VERSION 5.7 ;
  NOWIREEXTENSIONATPIN ON ;
  DIVIDERCHAR "/" ;
  BUSBITCHARS "[]" ;
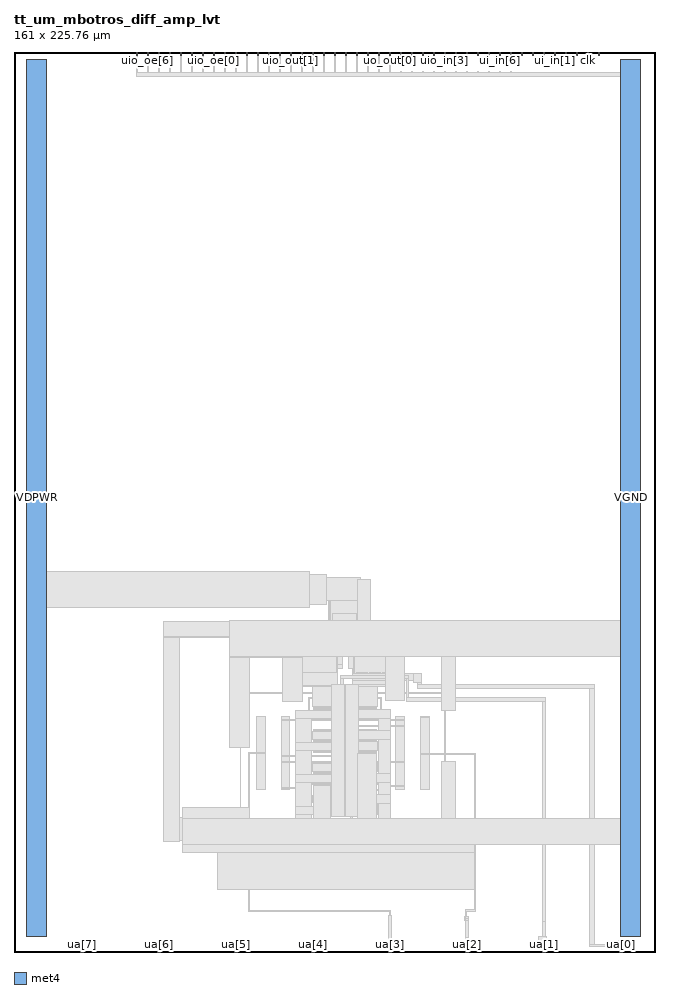
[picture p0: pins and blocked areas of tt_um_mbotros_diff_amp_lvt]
MACRO tt_um_mbotros_diff_amp_lvt
  CLASS BLOCK ;
  FOREIGN tt_um_mbotros_diff_amp_lvt ;
  ORIGIN 0.000 0.000 ;
  SIZE 161.000 BY 225.760 ;
  PIN clk
    DIRECTION INPUT ;
    USE SIGNAL ;
    PORT
      LAYER met4 ;
        RECT 143.830 224.760 144.130 225.760 ;
    END
  END clk
  PIN ena
    DIRECTION INPUT ;
    USE SIGNAL ;
    PORT
      LAYER met4 ;
        RECT 146.590 224.760 146.890 225.760 ;
    END
  END ena
  PIN rst_n
    DIRECTION INPUT ;
    USE SIGNAL ;
    PORT
      LAYER met4 ;
        RECT 141.070 224.760 141.370 225.760 ;
    END
  END rst_n
  PIN ua[0]
    DIRECTION INOUT ;
    USE SIGNAL ;
    ANTENNADIFFAREA 45.399998 ;
    PORT
      LAYER met4 ;
        RECT 151.810 0.000 152.710 1.000 ;
    END
  END ua[0]
  PIN ua[1]
    DIRECTION INOUT ;
    USE SIGNAL ;
    ANTENNADIFFAREA 42.500000 ;
    PORT
      LAYER met4 ;
        RECT 132.490 0.000 133.390 1.000 ;
    END
  END ua[1]
  PIN ua[2]
    DIRECTION INOUT ;
    USE SIGNAL ;
    PORT
      LAYER met4 ;
        RECT 113.170 0.000 114.070 1.000 ;
    END
  END ua[2]
  PIN ua[3]
    DIRECTION INOUT ;
    USE SIGNAL ;
    PORT
      LAYER met4 ;
        RECT 93.850 0.000 94.750 1.000 ;
    END
  END ua[3]
  PIN ua[4]
    DIRECTION INOUT ;
    USE SIGNAL ;
    PORT
      LAYER met4 ;
        RECT 74.530 0.000 75.430 1.000 ;
    END
  END ua[4]
  PIN ua[5]
    DIRECTION INOUT ;
    USE SIGNAL ;
    PORT
      LAYER met4 ;
        RECT 55.210 0.000 56.110 1.000 ;
    END
  END ua[5]
  PIN ua[6]
    DIRECTION INOUT ;
    USE SIGNAL ;
    PORT
      LAYER met4 ;
        RECT 35.890 0.000 36.790 1.000 ;
    END
  END ua[6]
  PIN ua[7]
    DIRECTION INOUT ;
    USE SIGNAL ;
    PORT
      LAYER met4 ;
        RECT 16.570 0.000 17.470 1.000 ;
    END
  END ua[7]
  PIN ui_in[0]
    DIRECTION INPUT ;
    USE SIGNAL ;
    PORT
      LAYER met4 ;
        RECT 138.310 224.760 138.610 225.760 ;
    END
  END ui_in[0]
  PIN ui_in[1]
    DIRECTION INPUT ;
    USE SIGNAL ;
    PORT
      LAYER met4 ;
        RECT 135.550 224.760 135.850 225.760 ;
    END
  END ui_in[1]
  PIN ui_in[2]
    DIRECTION INPUT ;
    USE SIGNAL ;
    PORT
      LAYER met4 ;
        RECT 132.790 224.760 133.090 225.760 ;
    END
  END ui_in[2]
  PIN ui_in[3]
    DIRECTION INPUT ;
    USE SIGNAL ;
    PORT
      LAYER met4 ;
        RECT 130.030 224.760 130.330 225.760 ;
    END
  END ui_in[3]
  PIN ui_in[4]
    DIRECTION INPUT ;
    USE SIGNAL ;
    PORT
      LAYER met4 ;
        RECT 127.270 224.760 127.570 225.760 ;
    END
  END ui_in[4]
  PIN ui_in[5]
    DIRECTION INPUT ;
    USE SIGNAL ;
    PORT
      LAYER met4 ;
        RECT 124.510 224.760 124.810 225.760 ;
    END
  END ui_in[5]
  PIN ui_in[6]
    DIRECTION INPUT ;
    USE SIGNAL ;
    PORT
      LAYER met4 ;
        RECT 121.750 224.760 122.050 225.760 ;
    END
  END ui_in[6]
  PIN ui_in[7]
    DIRECTION INPUT ;
    USE SIGNAL ;
    PORT
      LAYER met4 ;
        RECT 118.990 224.760 119.290 225.760 ;
    END
  END ui_in[7]
  PIN uio_in[0]
    DIRECTION INPUT ;
    USE SIGNAL ;
    PORT
      LAYER met4 ;
        RECT 116.230 224.760 116.530 225.760 ;
    END
  END uio_in[0]
  PIN uio_in[1]
    DIRECTION INPUT ;
    USE SIGNAL ;
    PORT
      LAYER met4 ;
        RECT 113.470 224.760 113.770 225.760 ;
    END
  END uio_in[1]
  PIN uio_in[2]
    DIRECTION INPUT ;
    USE SIGNAL ;
    PORT
      LAYER met4 ;
        RECT 110.710 224.760 111.010 225.760 ;
    END
  END uio_in[2]
  PIN uio_in[3]
    DIRECTION INPUT ;
    USE SIGNAL ;
    PORT
      LAYER met4 ;
        RECT 107.950 224.760 108.250 225.760 ;
    END
  END uio_in[3]
  PIN uio_in[4]
    DIRECTION INPUT ;
    USE SIGNAL ;
    PORT
      LAYER met4 ;
        RECT 105.190 224.760 105.490 225.760 ;
    END
  END uio_in[4]
  PIN uio_in[5]
    DIRECTION INPUT ;
    USE SIGNAL ;
    PORT
      LAYER met4 ;
        RECT 102.430 224.760 102.730 225.760 ;
    END
  END uio_in[5]
  PIN uio_in[6]
    DIRECTION INPUT ;
    USE SIGNAL ;
    PORT
      LAYER met4 ;
        RECT 99.670 224.760 99.970 225.760 ;
    END
  END uio_in[6]
  PIN uio_in[7]
    DIRECTION INPUT ;
    USE SIGNAL ;
    PORT
      LAYER met4 ;
        RECT 96.910 224.760 97.210 225.760 ;
    END
  END uio_in[7]
  PIN uio_oe[0]
    DIRECTION OUTPUT ;
    USE SIGNAL ;
    ANTENNADIFFAREA 129.679398 ;
    PORT
      LAYER met4 ;
        RECT 49.990 224.760 50.290 225.760 ;
    END
  END uio_oe[0]
  PIN uio_oe[1]
    DIRECTION OUTPUT ;
    USE SIGNAL ;
    ANTENNADIFFAREA 129.679398 ;
    PORT
      LAYER met4 ;
        RECT 47.230 224.760 47.530 225.760 ;
    END
  END uio_oe[1]
  PIN uio_oe[2]
    DIRECTION OUTPUT ;
    USE SIGNAL ;
    ANTENNADIFFAREA 129.679398 ;
    PORT
      LAYER met4 ;
        RECT 44.470 224.760 44.770 225.760 ;
    END
  END uio_oe[2]
  PIN uio_oe[3]
    DIRECTION OUTPUT ;
    USE SIGNAL ;
    ANTENNADIFFAREA 129.679398 ;
    PORT
      LAYER met4 ;
        RECT 41.710 224.760 42.010 225.760 ;
    END
  END uio_oe[3]
  PIN uio_oe[4]
    DIRECTION OUTPUT ;
    USE SIGNAL ;
    ANTENNADIFFAREA 129.679398 ;
    PORT
      LAYER met4 ;
        RECT 38.950 224.760 39.250 225.760 ;
    END
  END uio_oe[4]
  PIN uio_oe[5]
    DIRECTION OUTPUT ;
    USE SIGNAL ;
    ANTENNADIFFAREA 129.679398 ;
    PORT
      LAYER met4 ;
        RECT 36.190 224.760 36.490 225.760 ;
    END
  END uio_oe[5]
  PIN uio_oe[6]
    DIRECTION OUTPUT ;
    USE SIGNAL ;
    ANTENNADIFFAREA 129.679398 ;
    PORT
      LAYER met4 ;
        RECT 33.430 224.760 33.730 225.760 ;
    END
  END uio_oe[6]
  PIN uio_oe[7]
    DIRECTION OUTPUT ;
    USE SIGNAL ;
    ANTENNADIFFAREA 129.679398 ;
    PORT
      LAYER met4 ;
        RECT 30.670 224.760 30.970 225.760 ;
    END
  END uio_oe[7]
  PIN uio_out[0]
    DIRECTION OUTPUT ;
    USE SIGNAL ;
    ANTENNADIFFAREA 129.679398 ;
    PORT
      LAYER met4 ;
        RECT 72.070 224.760 72.370 225.760 ;
    END
  END uio_out[0]
  PIN uio_out[1]
    DIRECTION OUTPUT ;
    USE SIGNAL ;
    ANTENNADIFFAREA 129.679398 ;
    PORT
      LAYER met4 ;
        RECT 69.310 224.760 69.610 225.760 ;
    END
  END uio_out[1]
  PIN uio_out[2]
    DIRECTION OUTPUT ;
    USE SIGNAL ;
    ANTENNADIFFAREA 129.679398 ;
    PORT
      LAYER met4 ;
        RECT 66.550 224.760 66.850 225.760 ;
    END
  END uio_out[2]
  PIN uio_out[3]
    DIRECTION OUTPUT ;
    USE SIGNAL ;
    ANTENNADIFFAREA 129.679398 ;
    PORT
      LAYER met4 ;
        RECT 63.790 224.760 64.090 225.760 ;
    END
  END uio_out[3]
  PIN uio_out[4]
    DIRECTION OUTPUT ;
    USE SIGNAL ;
    ANTENNADIFFAREA 129.679398 ;
    PORT
      LAYER met4 ;
        RECT 61.030 224.760 61.330 225.760 ;
    END
  END uio_out[4]
  PIN uio_out[5]
    DIRECTION OUTPUT ;
    USE SIGNAL ;
    ANTENNADIFFAREA 129.679398 ;
    PORT
      LAYER met4 ;
        RECT 58.270 224.760 58.570 225.760 ;
    END
  END uio_out[5]
  PIN uio_out[6]
    DIRECTION OUTPUT ;
    USE SIGNAL ;
    ANTENNADIFFAREA 129.679398 ;
    PORT
      LAYER met4 ;
        RECT 55.510 224.760 55.810 225.760 ;
    END
  END uio_out[6]
  PIN uio_out[7]
    DIRECTION OUTPUT ;
    USE SIGNAL ;
    ANTENNADIFFAREA 129.679398 ;
    PORT
      LAYER met4 ;
        RECT 52.750 224.760 53.050 225.760 ;
    END
  END uio_out[7]
  PIN uo_out[0]
    DIRECTION OUTPUT ;
    USE SIGNAL ;
    ANTENNADIFFAREA 129.679398 ;
    PORT
      LAYER met4 ;
        RECT 94.150 224.760 94.450 225.760 ;
    END
  END uo_out[0]
  PIN uo_out[1]
    DIRECTION OUTPUT ;
    USE SIGNAL ;
    ANTENNADIFFAREA 129.679398 ;
    PORT
      LAYER met4 ;
        RECT 91.390 224.760 91.690 225.760 ;
    END
  END uo_out[1]
  PIN uo_out[2]
    DIRECTION OUTPUT ;
    USE SIGNAL ;
    ANTENNADIFFAREA 129.679398 ;
    PORT
      LAYER met4 ;
        RECT 88.630 224.760 88.930 225.760 ;
    END
  END uo_out[2]
  PIN uo_out[3]
    DIRECTION OUTPUT ;
    USE SIGNAL ;
    ANTENNADIFFAREA 129.679398 ;
    PORT
      LAYER met4 ;
        RECT 85.870 224.760 86.170 225.760 ;
    END
  END uo_out[3]
  PIN uo_out[4]
    DIRECTION OUTPUT ;
    USE SIGNAL ;
    ANTENNADIFFAREA 129.679398 ;
    PORT
      LAYER met4 ;
        RECT 83.110 224.760 83.410 225.760 ;
    END
  END uo_out[4]
  PIN uo_out[5]
    DIRECTION OUTPUT ;
    USE SIGNAL ;
    ANTENNADIFFAREA 129.679398 ;
    PORT
      LAYER met4 ;
        RECT 80.350 224.760 80.650 225.760 ;
    END
  END uo_out[5]
  PIN uo_out[6]
    DIRECTION OUTPUT ;
    USE SIGNAL ;
    ANTENNADIFFAREA 129.679398 ;
    PORT
      LAYER met4 ;
        RECT 77.590 224.760 77.890 225.760 ;
    END
  END uo_out[6]
  PIN uo_out[7]
    DIRECTION OUTPUT ;
    USE SIGNAL ;
    ANTENNADIFFAREA 129.679398 ;
    PORT
      LAYER met4 ;
        RECT 74.830 224.760 75.130 225.760 ;
    END
  END uo_out[7]
  PIN VGND
    DIRECTION INOUT ;
    USE GROUND ;
    PORT
      LAYER met4 ;
        RECT 152.250 3.900 157.250 223.900 ;
    END
  END VGND
  PIN VDPWR
    DIRECTION INOUT ;
    USE POWER ;
    PORT
      LAYER met4 ;
        RECT 3.100 3.900 8.100 223.900 ;
    END
  END VDPWR
  OBS
      LAYER pwell ;
        RECT 79.000 82.000 86.840 92.430 ;
        RECT 70.000 67.000 81.170 78.540 ;
        RECT 85.000 67.000 96.170 78.540 ;
        RECT 42.520 27.045 54.940 34.435 ;
      LAYER li1 ;
        RECT 79.180 92.080 86.660 92.250 ;
        RECT 79.180 83.180 79.350 92.080 ;
        RECT 86.490 91.940 86.660 92.080 ;
        RECT 79.830 89.440 82.680 91.600 ;
        RECT 83.160 89.440 86.010 91.600 ;
        RECT 86.490 90.940 87.920 91.940 ;
        RECT 77.860 82.350 79.350 83.180 ;
        RECT 79.830 82.830 82.680 84.990 ;
        RECT 83.160 82.830 86.010 84.990 ;
        RECT 86.490 83.200 86.660 90.940 ;
        RECT 86.490 82.350 87.980 83.200 ;
        RECT 77.860 82.200 87.980 82.350 ;
        RECT 77.860 82.180 86.660 82.200 ;
        RECT 69.060 78.360 70.260 78.430 ;
        RECT 95.900 78.360 97.180 78.630 ;
        RECT 69.060 78.190 80.990 78.360 ;
        RECT 69.060 77.560 70.350 78.190 ;
        RECT 70.180 68.400 70.350 77.560 ;
        RECT 70.830 75.550 73.680 77.710 ;
        RECT 74.160 75.550 77.010 77.710 ;
        RECT 77.490 75.550 80.340 77.710 ;
        RECT 80.820 72.240 80.990 78.190 ;
        RECT 85.180 78.190 97.180 78.360 ;
        RECT 85.180 72.260 85.350 78.190 ;
        RECT 85.830 75.550 88.680 77.710 ;
        RECT 89.160 75.550 92.010 77.710 ;
        RECT 92.490 75.550 95.340 77.710 ;
        RECT 95.820 77.690 97.180 78.190 ;
        RECT 80.820 71.370 82.150 72.240 ;
        RECT 69.000 67.350 70.350 68.400 ;
        RECT 70.830 67.830 73.680 69.990 ;
        RECT 74.160 67.830 77.010 69.990 ;
        RECT 77.490 67.830 80.340 69.990 ;
        RECT 80.820 67.350 80.990 71.370 ;
        RECT 84.140 71.340 85.350 72.260 ;
        RECT 69.000 67.190 80.990 67.350 ;
        RECT 70.180 67.180 80.990 67.190 ;
        RECT 85.180 67.350 85.350 71.340 ;
        RECT 85.830 67.830 88.680 69.990 ;
        RECT 89.160 67.830 92.010 69.990 ;
        RECT 92.490 67.830 95.340 69.990 ;
        RECT 95.820 67.680 95.990 77.690 ;
        RECT 95.820 67.350 97.260 67.680 ;
        RECT 85.180 67.180 97.260 67.350 ;
        RECT 95.900 66.680 97.260 67.180 ;
        RECT 56.735 64.855 108.185 65.025 ;
        RECT 56.735 64.800 56.905 64.855 ;
        RECT 55.550 63.590 56.905 64.800 ;
        RECT 70.160 63.740 71.460 64.855 ;
        RECT 75.145 63.630 80.905 63.800 ;
        RECT 85.145 63.630 90.905 63.800 ;
        RECT 93.890 63.760 95.190 64.855 ;
        RECT 56.735 53.580 56.905 63.590 ;
        RECT 55.570 52.370 56.905 53.580 ;
        RECT 60.830 53.250 62.990 58.980 ;
        RECT 66.990 53.250 69.150 58.980 ;
        RECT 75.060 58.420 75.230 63.460 ;
        RECT 75.540 58.420 75.710 63.460 ;
        RECT 76.020 58.420 76.190 63.460 ;
        RECT 76.500 58.420 76.670 63.460 ;
        RECT 76.980 58.420 77.150 63.460 ;
        RECT 77.460 58.420 77.630 63.460 ;
        RECT 77.940 58.420 78.110 63.460 ;
        RECT 78.420 58.420 78.590 63.460 ;
        RECT 78.900 58.420 79.070 63.460 ;
        RECT 79.380 58.420 79.550 63.460 ;
        RECT 79.860 58.420 80.030 63.460 ;
        RECT 80.340 58.420 80.510 63.460 ;
        RECT 80.820 58.420 80.990 63.460 ;
        RECT 85.060 58.420 85.230 63.460 ;
        RECT 85.540 58.420 85.710 63.460 ;
        RECT 86.020 58.420 86.190 63.460 ;
        RECT 86.500 58.420 86.670 63.460 ;
        RECT 86.980 58.420 87.150 63.460 ;
        RECT 87.460 58.420 87.630 63.460 ;
        RECT 87.940 58.420 88.110 63.460 ;
        RECT 88.420 58.420 88.590 63.460 ;
        RECT 88.900 58.420 89.070 63.460 ;
        RECT 89.380 58.420 89.550 63.460 ;
        RECT 89.860 58.420 90.030 63.460 ;
        RECT 90.340 58.420 90.510 63.460 ;
        RECT 90.820 58.420 90.990 63.460 ;
        RECT 108.015 62.690 108.185 64.855 ;
        RECT 108.015 61.480 109.390 62.690 ;
        RECT 75.145 58.080 80.905 58.250 ;
        RECT 85.145 58.080 90.905 58.250 ;
        RECT 75.145 55.630 80.905 55.800 ;
        RECT 85.145 55.630 90.905 55.800 ;
        RECT 42.700 34.255 43.670 35.340 ;
        RECT 56.735 34.740 56.905 52.370 ;
        RECT 60.830 47.040 62.990 52.770 ;
        RECT 66.990 47.040 69.150 52.770 ;
        RECT 75.060 50.420 75.230 55.460 ;
        RECT 75.540 50.420 75.710 55.460 ;
        RECT 76.020 50.420 76.190 55.460 ;
        RECT 76.500 50.420 76.670 55.460 ;
        RECT 76.980 50.420 77.150 55.460 ;
        RECT 77.460 50.420 77.630 55.460 ;
        RECT 77.940 50.420 78.110 55.460 ;
        RECT 78.420 50.420 78.590 55.460 ;
        RECT 78.900 50.420 79.070 55.460 ;
        RECT 79.380 50.420 79.550 55.460 ;
        RECT 79.860 50.420 80.030 55.460 ;
        RECT 80.340 50.420 80.510 55.460 ;
        RECT 80.820 50.420 80.990 55.460 ;
        RECT 85.060 50.420 85.230 55.460 ;
        RECT 85.540 50.420 85.710 55.460 ;
        RECT 86.020 50.420 86.190 55.460 ;
        RECT 86.500 50.420 86.670 55.460 ;
        RECT 86.980 50.420 87.150 55.460 ;
        RECT 87.460 50.420 87.630 55.460 ;
        RECT 87.940 50.420 88.110 55.460 ;
        RECT 88.420 50.420 88.590 55.460 ;
        RECT 88.900 50.420 89.070 55.460 ;
        RECT 89.380 50.420 89.550 55.460 ;
        RECT 89.860 50.420 90.030 55.460 ;
        RECT 90.340 50.420 90.510 55.460 ;
        RECT 90.820 50.420 90.990 55.460 ;
        RECT 95.830 53.250 97.990 58.980 ;
        RECT 101.990 53.250 104.150 58.980 ;
        RECT 75.145 50.080 80.905 50.250 ;
        RECT 85.145 50.080 90.905 50.250 ;
        RECT 87.850 48.540 89.210 49.410 ;
        RECT 75.145 47.630 80.905 47.800 ;
        RECT 85.145 47.630 90.905 47.800 ;
        RECT 60.830 40.830 62.990 46.560 ;
        RECT 66.990 40.830 69.150 46.560 ;
        RECT 75.060 42.420 75.230 47.460 ;
        RECT 75.540 42.420 75.710 47.460 ;
        RECT 76.020 42.420 76.190 47.460 ;
        RECT 76.500 42.420 76.670 47.460 ;
        RECT 76.980 42.420 77.150 47.460 ;
        RECT 77.460 42.420 77.630 47.460 ;
        RECT 77.940 42.420 78.110 47.460 ;
        RECT 78.420 42.420 78.590 47.460 ;
        RECT 78.900 42.420 79.070 47.460 ;
        RECT 79.380 42.420 79.550 47.460 ;
        RECT 79.860 42.420 80.030 47.460 ;
        RECT 80.340 42.420 80.510 47.460 ;
        RECT 80.820 42.420 80.990 47.460 ;
        RECT 85.060 42.420 85.230 47.460 ;
        RECT 85.540 42.420 85.710 47.460 ;
        RECT 86.020 42.420 86.190 47.460 ;
        RECT 86.500 42.420 86.670 47.460 ;
        RECT 86.980 42.420 87.150 47.460 ;
        RECT 87.460 42.420 87.630 47.460 ;
        RECT 87.940 42.420 88.110 47.460 ;
        RECT 88.420 42.420 88.590 47.460 ;
        RECT 88.900 42.420 89.070 47.460 ;
        RECT 89.380 42.420 89.550 47.460 ;
        RECT 89.860 42.420 90.030 47.460 ;
        RECT 90.340 42.420 90.510 47.460 ;
        RECT 90.820 42.420 90.990 47.460 ;
        RECT 95.830 47.040 97.990 52.770 ;
        RECT 101.990 47.040 104.150 52.770 ;
        RECT 108.015 47.280 108.185 61.480 ;
        RECT 75.145 42.080 80.905 42.250 ;
        RECT 85.145 42.080 90.905 42.250 ;
        RECT 76.870 40.470 78.230 41.340 ;
        RECT 95.830 40.830 97.990 46.560 ;
        RECT 101.990 40.830 104.150 46.560 ;
        RECT 108.015 46.070 109.420 47.280 ;
        RECT 75.145 39.630 80.905 39.800 ;
        RECT 85.145 39.630 90.905 39.800 ;
        RECT 54.610 34.255 56.905 34.740 ;
        RECT 75.060 34.420 75.230 39.460 ;
        RECT 75.540 34.420 75.710 39.460 ;
        RECT 76.020 34.420 76.190 39.460 ;
        RECT 76.500 34.420 76.670 39.460 ;
        RECT 76.980 34.420 77.150 39.460 ;
        RECT 77.460 34.420 77.630 39.460 ;
        RECT 77.940 34.420 78.110 39.460 ;
        RECT 78.420 34.420 78.590 39.460 ;
        RECT 78.900 34.420 79.070 39.460 ;
        RECT 79.380 34.420 79.550 39.460 ;
        RECT 79.860 34.420 80.030 39.460 ;
        RECT 80.340 34.420 80.510 39.460 ;
        RECT 80.820 34.420 80.990 39.460 ;
        RECT 85.060 34.420 85.230 39.460 ;
        RECT 85.540 34.420 85.710 39.460 ;
        RECT 86.020 34.420 86.190 39.460 ;
        RECT 86.500 34.420 86.670 39.460 ;
        RECT 86.980 34.420 87.150 39.460 ;
        RECT 87.460 34.420 87.630 39.460 ;
        RECT 87.940 34.420 88.110 39.460 ;
        RECT 88.420 34.420 88.590 39.460 ;
        RECT 88.900 34.420 89.070 39.460 ;
        RECT 89.380 34.420 89.550 39.460 ;
        RECT 89.860 34.420 90.030 39.460 ;
        RECT 90.340 34.420 90.510 39.460 ;
        RECT 90.820 34.420 90.990 39.460 ;
        RECT 42.700 34.085 56.905 34.255 ;
        RECT 42.700 27.395 42.870 34.085 ;
        RECT 54.590 33.830 56.905 34.085 ;
        RECT 75.145 34.080 80.905 34.250 ;
        RECT 85.145 34.080 90.905 34.250 ;
        RECT 43.350 27.875 45.510 33.605 ;
        RECT 51.950 27.875 54.110 33.605 ;
        RECT 54.590 27.395 54.760 33.830 ;
        RECT 56.735 31.160 56.905 33.830 ;
        RECT 108.015 33.440 108.185 46.070 ;
        RECT 108.015 32.230 109.400 33.440 ;
        RECT 56.735 30.095 58.050 31.160 ;
        RECT 108.015 30.095 108.185 32.230 ;
        RECT 56.735 29.925 108.185 30.095 ;
        RECT 42.700 27.225 54.760 27.395 ;
        RECT 42.700 26.110 43.670 27.225 ;
        RECT 56.220 26.385 57.390 27.540 ;
        RECT 114.130 26.385 115.250 27.040 ;
        RECT 51.085 26.215 115.250 26.385 ;
        RECT 51.085 17.515 51.255 26.215 ;
        RECT 52.080 20.145 52.250 25.675 ;
        RECT 52.420 25.590 57.460 25.760 ;
        RECT 52.420 24.800 57.460 24.970 ;
        RECT 52.420 24.010 57.460 24.180 ;
        RECT 52.420 23.220 57.460 23.390 ;
        RECT 52.420 22.430 57.460 22.600 ;
        RECT 52.420 21.640 57.460 21.810 ;
        RECT 52.420 20.850 57.460 21.020 ;
        RECT 52.420 20.060 57.460 20.230 ;
        RECT 57.630 20.145 57.800 25.675 ;
        RECT 60.080 20.145 60.250 25.675 ;
        RECT 60.420 25.590 65.460 25.760 ;
        RECT 60.420 24.800 65.460 24.970 ;
        RECT 60.420 24.010 65.460 24.180 ;
        RECT 60.420 23.220 65.460 23.390 ;
        RECT 60.420 22.430 65.460 22.600 ;
        RECT 60.420 21.640 65.460 21.810 ;
        RECT 60.420 20.850 65.460 21.020 ;
        RECT 60.420 20.060 65.460 20.230 ;
        RECT 65.630 20.145 65.800 25.675 ;
        RECT 68.080 20.145 68.250 25.675 ;
        RECT 68.420 25.590 73.460 25.760 ;
        RECT 68.420 24.800 73.460 24.970 ;
        RECT 68.420 24.010 73.460 24.180 ;
        RECT 68.420 23.220 73.460 23.390 ;
        RECT 68.420 22.430 73.460 22.600 ;
        RECT 68.420 21.640 73.460 21.810 ;
        RECT 68.420 20.850 73.460 21.020 ;
        RECT 68.420 20.060 73.460 20.230 ;
        RECT 73.630 20.145 73.800 25.675 ;
        RECT 76.080 20.145 76.250 25.675 ;
        RECT 76.420 25.590 81.460 25.760 ;
        RECT 76.420 24.800 81.460 24.970 ;
        RECT 76.420 24.010 81.460 24.180 ;
        RECT 76.420 23.220 81.460 23.390 ;
        RECT 76.420 22.430 81.460 22.600 ;
        RECT 76.420 21.640 81.460 21.810 ;
        RECT 76.420 20.850 81.460 21.020 ;
        RECT 76.420 20.060 81.460 20.230 ;
        RECT 81.630 20.145 81.800 25.675 ;
        RECT 82.340 25.040 83.510 26.215 ;
        RECT 84.080 20.145 84.250 25.675 ;
        RECT 84.420 25.590 89.460 25.760 ;
        RECT 84.420 24.800 89.460 24.970 ;
        RECT 84.420 24.010 89.460 24.180 ;
        RECT 84.420 23.220 89.460 23.390 ;
        RECT 84.420 22.430 89.460 22.600 ;
        RECT 84.420 21.640 89.460 21.810 ;
        RECT 84.420 20.850 89.460 21.020 ;
        RECT 84.420 20.060 89.460 20.230 ;
        RECT 89.630 20.145 89.800 25.675 ;
        RECT 92.080 20.145 92.250 25.675 ;
        RECT 92.420 25.590 97.460 25.760 ;
        RECT 92.420 24.800 97.460 24.970 ;
        RECT 92.420 24.010 97.460 24.180 ;
        RECT 92.420 23.220 97.460 23.390 ;
        RECT 92.420 22.430 97.460 22.600 ;
        RECT 92.420 21.640 97.460 21.810 ;
        RECT 92.420 20.850 97.460 21.020 ;
        RECT 92.420 20.060 97.460 20.230 ;
        RECT 97.630 20.145 97.800 25.675 ;
        RECT 100.080 20.145 100.250 25.675 ;
        RECT 100.420 25.590 105.460 25.760 ;
        RECT 100.420 24.800 105.460 24.970 ;
        RECT 100.420 24.010 105.460 24.180 ;
        RECT 100.420 23.220 105.460 23.390 ;
        RECT 100.420 22.430 105.460 22.600 ;
        RECT 100.420 21.640 105.460 21.810 ;
        RECT 100.420 20.850 105.460 21.020 ;
        RECT 100.420 20.060 105.460 20.230 ;
        RECT 105.630 20.145 105.800 25.675 ;
        RECT 108.080 20.145 108.250 25.675 ;
        RECT 108.420 25.590 113.460 25.760 ;
        RECT 108.420 24.800 113.460 24.970 ;
        RECT 108.420 24.010 113.460 24.180 ;
        RECT 108.420 23.220 113.460 23.390 ;
        RECT 108.420 22.430 113.460 22.600 ;
        RECT 108.420 21.640 113.460 21.810 ;
        RECT 108.420 20.850 113.460 21.020 ;
        RECT 108.420 20.060 113.460 20.230 ;
        RECT 113.630 20.145 113.800 25.675 ;
        RECT 114.130 25.520 115.250 26.215 ;
        RECT 114.315 17.520 114.485 25.520 ;
        RECT 113.010 17.515 114.485 17.520 ;
        RECT 51.085 17.345 114.485 17.515 ;
        RECT 51.390 16.200 52.730 17.345 ;
        RECT 63.550 16.180 64.800 17.345 ;
        RECT 78.870 16.220 80.100 17.345 ;
        RECT 97.130 16.290 98.460 17.345 ;
        RECT 113.010 16.380 114.340 17.345 ;
      LAYER met1 ;
        RECT 86.560 91.930 87.920 91.940 ;
        RECT 79.850 89.495 82.660 91.540 ;
        RECT 83.180 89.495 85.990 91.540 ;
        RECT 86.560 90.940 88.330 91.930 ;
        RECT 87.240 90.930 88.330 90.940 ;
        RECT 77.860 82.180 79.220 83.180 ;
        RECT 79.850 82.890 82.660 84.935 ;
        RECT 83.180 82.890 85.990 84.935 ;
        RECT 86.620 82.200 87.980 83.200 ;
        RECT 96.200 78.630 97.130 78.640 ;
        RECT 69.060 77.560 70.260 78.430 ;
        RECT 95.900 77.690 97.180 78.630 ;
        RECT 96.200 77.660 97.130 77.690 ;
        RECT 70.850 75.605 73.660 77.650 ;
        RECT 74.180 75.605 76.990 77.650 ;
        RECT 77.510 75.605 80.320 77.650 ;
        RECT 85.850 75.605 88.660 77.650 ;
        RECT 89.180 75.605 91.990 77.650 ;
        RECT 92.510 75.605 95.320 77.650 ;
        RECT 80.950 71.370 82.150 72.240 ;
        RECT 84.140 71.340 85.230 72.260 ;
        RECT 69.000 67.190 70.300 68.400 ;
        RECT 70.850 67.890 73.660 69.935 ;
        RECT 74.180 67.890 76.990 69.935 ;
        RECT 77.510 67.890 80.320 69.935 ;
        RECT 85.850 67.890 88.660 69.935 ;
        RECT 89.180 67.890 91.990 69.935 ;
        RECT 92.510 67.890 95.320 69.935 ;
        RECT 96.310 67.680 97.240 67.760 ;
        RECT 95.900 66.680 97.260 67.680 ;
        RECT 55.550 63.590 56.850 64.800 ;
        RECT 70.160 63.740 71.460 64.950 ;
        RECT 73.915 63.580 80.915 63.880 ;
        RECT 85.150 63.800 92.150 63.880 ;
        RECT 85.145 63.630 92.150 63.800 ;
        RECT 93.890 63.760 95.190 64.970 ;
        RECT 85.150 63.580 92.150 63.630 ;
        RECT 55.570 52.370 56.870 53.580 ;
        RECT 60.890 53.270 62.935 58.960 ;
        RECT 66.980 58.300 69.160 58.990 ;
        RECT 73.915 58.300 74.215 63.580 ;
        RECT 75.030 63.135 75.260 63.440 ;
        RECT 74.950 62.875 75.310 63.135 ;
        RECT 75.030 62.560 75.260 62.875 ;
        RECT 74.950 62.300 75.310 62.560 ;
        RECT 75.030 61.950 75.260 62.300 ;
        RECT 74.950 61.690 75.310 61.950 ;
        RECT 75.030 58.440 75.260 61.690 ;
        RECT 75.510 60.435 75.740 63.440 ;
        RECT 75.990 63.130 76.220 63.440 ;
        RECT 75.925 62.870 76.285 63.130 ;
        RECT 75.990 62.565 76.220 62.870 ;
        RECT 75.925 62.305 76.285 62.565 ;
        RECT 75.990 61.955 76.220 62.305 ;
        RECT 75.925 61.695 76.285 61.955 ;
        RECT 75.445 60.175 75.805 60.435 ;
        RECT 75.510 59.720 75.740 60.175 ;
        RECT 75.445 59.460 75.805 59.720 ;
        RECT 75.510 59.040 75.740 59.460 ;
        RECT 75.445 58.780 75.805 59.040 ;
        RECT 75.510 58.440 75.740 58.780 ;
        RECT 75.990 58.440 76.220 61.695 ;
        RECT 76.470 60.435 76.700 63.440 ;
        RECT 76.950 63.130 77.180 63.440 ;
        RECT 76.885 62.870 77.245 63.130 ;
        RECT 76.950 62.565 77.180 62.870 ;
        RECT 76.885 62.305 77.245 62.565 ;
        RECT 76.950 61.955 77.180 62.305 ;
        RECT 76.885 61.695 77.245 61.955 ;
        RECT 76.405 60.175 76.765 60.435 ;
        RECT 76.470 59.720 76.700 60.175 ;
        RECT 76.405 59.460 76.765 59.720 ;
        RECT 76.470 59.040 76.700 59.460 ;
        RECT 76.405 58.780 76.765 59.040 ;
        RECT 76.470 58.440 76.700 58.780 ;
        RECT 76.950 58.440 77.180 61.695 ;
        RECT 77.430 60.435 77.660 63.440 ;
        RECT 77.910 63.130 78.140 63.440 ;
        RECT 77.845 62.870 78.205 63.130 ;
        RECT 77.910 62.565 78.140 62.870 ;
        RECT 77.845 62.305 78.205 62.565 ;
        RECT 77.910 61.955 78.140 62.305 ;
        RECT 77.845 61.695 78.205 61.955 ;
        RECT 77.365 60.175 77.725 60.435 ;
        RECT 77.430 59.720 77.660 60.175 ;
        RECT 77.365 59.460 77.725 59.720 ;
        RECT 77.430 59.040 77.660 59.460 ;
        RECT 77.365 58.780 77.725 59.040 ;
        RECT 77.430 58.440 77.660 58.780 ;
        RECT 77.910 58.440 78.140 61.695 ;
        RECT 78.390 60.435 78.620 63.440 ;
        RECT 78.870 63.130 79.100 63.440 ;
        RECT 78.805 62.870 79.165 63.130 ;
        RECT 78.870 62.565 79.100 62.870 ;
        RECT 78.805 62.305 79.165 62.565 ;
        RECT 78.870 61.955 79.100 62.305 ;
        RECT 78.805 61.695 79.165 61.955 ;
        RECT 78.325 60.175 78.685 60.435 ;
        RECT 78.390 59.720 78.620 60.175 ;
        RECT 78.325 59.460 78.685 59.720 ;
        RECT 78.390 59.040 78.620 59.460 ;
        RECT 78.325 58.780 78.685 59.040 ;
        RECT 78.390 58.440 78.620 58.780 ;
        RECT 78.870 58.440 79.100 61.695 ;
        RECT 79.350 60.435 79.580 63.440 ;
        RECT 79.830 63.130 80.060 63.440 ;
        RECT 79.765 62.870 80.125 63.130 ;
        RECT 79.830 62.565 80.060 62.870 ;
        RECT 79.770 62.305 80.130 62.565 ;
        RECT 79.830 61.955 80.060 62.305 ;
        RECT 79.765 61.695 80.125 61.955 ;
        RECT 79.285 60.175 79.645 60.435 ;
        RECT 79.350 59.720 79.580 60.175 ;
        RECT 79.285 59.460 79.645 59.720 ;
        RECT 79.350 59.040 79.580 59.460 ;
        RECT 79.285 58.780 79.645 59.040 ;
        RECT 79.350 58.440 79.580 58.780 ;
        RECT 79.830 58.440 80.060 61.695 ;
        RECT 80.310 60.435 80.540 63.440 ;
        RECT 80.790 63.130 81.020 63.440 ;
        RECT 85.030 63.135 85.260 63.440 ;
        RECT 80.725 62.870 81.085 63.130 ;
        RECT 84.950 62.875 85.310 63.135 ;
        RECT 80.790 62.565 81.020 62.870 ;
        RECT 80.725 62.305 81.085 62.565 ;
        RECT 85.030 62.560 85.260 62.875 ;
        RECT 80.790 61.955 81.020 62.305 ;
        RECT 84.950 62.300 85.310 62.560 ;
        RECT 80.720 61.695 81.080 61.955 ;
        RECT 85.030 61.950 85.260 62.300 ;
        RECT 80.250 60.175 80.610 60.435 ;
        RECT 80.310 59.720 80.540 60.175 ;
        RECT 80.245 59.460 80.605 59.720 ;
        RECT 80.310 59.040 80.540 59.460 ;
        RECT 80.250 58.780 80.610 59.040 ;
        RECT 80.310 58.440 80.540 58.780 ;
        RECT 80.790 58.440 81.020 61.695 ;
        RECT 84.950 61.690 85.310 61.950 ;
        RECT 85.030 58.440 85.260 61.690 ;
        RECT 85.510 60.435 85.740 63.440 ;
        RECT 85.990 63.130 86.220 63.440 ;
        RECT 85.925 62.870 86.285 63.130 ;
        RECT 85.990 62.565 86.220 62.870 ;
        RECT 85.925 62.305 86.285 62.565 ;
        RECT 85.990 61.955 86.220 62.305 ;
        RECT 85.925 61.695 86.285 61.955 ;
        RECT 85.445 60.175 85.805 60.435 ;
        RECT 85.510 59.720 85.740 60.175 ;
        RECT 85.445 59.460 85.805 59.720 ;
        RECT 85.510 59.040 85.740 59.460 ;
        RECT 85.445 58.780 85.805 59.040 ;
        RECT 85.510 58.440 85.740 58.780 ;
        RECT 85.990 58.440 86.220 61.695 ;
        RECT 86.470 60.435 86.700 63.440 ;
        RECT 86.950 63.130 87.180 63.440 ;
        RECT 86.885 62.870 87.245 63.130 ;
        RECT 86.950 62.565 87.180 62.870 ;
        RECT 86.885 62.305 87.245 62.565 ;
        RECT 86.950 61.955 87.180 62.305 ;
        RECT 86.885 61.695 87.245 61.955 ;
        RECT 86.405 60.175 86.765 60.435 ;
        RECT 86.470 59.720 86.700 60.175 ;
        RECT 86.405 59.460 86.765 59.720 ;
        RECT 86.470 59.040 86.700 59.460 ;
        RECT 86.405 58.780 86.765 59.040 ;
        RECT 86.470 58.440 86.700 58.780 ;
        RECT 86.950 58.440 87.180 61.695 ;
        RECT 87.430 60.435 87.660 63.440 ;
        RECT 87.910 63.130 88.140 63.440 ;
        RECT 87.845 62.870 88.205 63.130 ;
        RECT 87.910 62.565 88.140 62.870 ;
        RECT 87.845 62.305 88.205 62.565 ;
        RECT 87.910 61.955 88.140 62.305 ;
        RECT 87.845 61.695 88.205 61.955 ;
        RECT 87.365 60.175 87.725 60.435 ;
        RECT 87.430 59.720 87.660 60.175 ;
        RECT 87.365 59.460 87.725 59.720 ;
        RECT 87.430 59.040 87.660 59.460 ;
        RECT 87.365 58.780 87.725 59.040 ;
        RECT 87.430 58.440 87.660 58.780 ;
        RECT 87.910 58.440 88.140 61.695 ;
        RECT 88.390 60.435 88.620 63.440 ;
        RECT 88.870 63.130 89.100 63.440 ;
        RECT 88.805 62.870 89.165 63.130 ;
        RECT 88.870 62.565 89.100 62.870 ;
        RECT 88.805 62.305 89.165 62.565 ;
        RECT 88.870 61.955 89.100 62.305 ;
        RECT 88.805 61.695 89.165 61.955 ;
        RECT 88.325 60.175 88.685 60.435 ;
        RECT 88.390 59.720 88.620 60.175 ;
        RECT 88.325 59.460 88.685 59.720 ;
        RECT 88.390 59.040 88.620 59.460 ;
        RECT 88.325 58.780 88.685 59.040 ;
        RECT 88.390 58.440 88.620 58.780 ;
        RECT 88.870 58.440 89.100 61.695 ;
        RECT 89.350 60.435 89.580 63.440 ;
        RECT 89.830 63.130 90.060 63.440 ;
        RECT 89.765 62.870 90.125 63.130 ;
        RECT 89.830 62.565 90.060 62.870 ;
        RECT 89.770 62.305 90.130 62.565 ;
        RECT 89.830 61.955 90.060 62.305 ;
        RECT 89.765 61.695 90.125 61.955 ;
        RECT 89.285 60.175 89.645 60.435 ;
        RECT 89.350 59.720 89.580 60.175 ;
        RECT 89.285 59.460 89.645 59.720 ;
        RECT 89.350 59.040 89.580 59.460 ;
        RECT 89.285 58.780 89.645 59.040 ;
        RECT 89.350 58.440 89.580 58.780 ;
        RECT 89.830 58.440 90.060 61.695 ;
        RECT 90.310 60.435 90.540 63.440 ;
        RECT 90.790 63.130 91.020 63.440 ;
        RECT 90.725 62.870 91.085 63.130 ;
        RECT 90.790 62.565 91.020 62.870 ;
        RECT 90.725 62.305 91.085 62.565 ;
        RECT 90.790 61.955 91.020 62.305 ;
        RECT 90.720 61.695 91.080 61.955 ;
        RECT 90.250 60.175 90.610 60.435 ;
        RECT 90.310 59.720 90.540 60.175 ;
        RECT 90.245 59.460 90.605 59.720 ;
        RECT 90.310 59.040 90.540 59.460 ;
        RECT 90.250 58.780 90.610 59.040 ;
        RECT 90.310 58.440 90.540 58.780 ;
        RECT 90.790 58.440 91.020 61.695 ;
        RECT 91.850 58.300 92.150 63.580 ;
        RECT 108.090 61.480 109.390 62.690 ;
        RECT 95.820 58.300 97.980 58.990 ;
        RECT 66.980 58.000 80.915 58.300 ;
        RECT 85.100 58.000 97.980 58.300 ;
        RECT 60.890 47.060 62.935 52.750 ;
        RECT 66.980 49.300 69.160 58.000 ;
        RECT 95.820 56.875 97.980 58.000 ;
        RECT 81.230 56.575 97.980 56.875 ;
        RECT 81.230 55.880 81.530 56.575 ;
        RECT 75.145 55.580 81.530 55.880 ;
        RECT 75.030 55.135 75.260 55.440 ;
        RECT 74.950 54.875 75.310 55.135 ;
        RECT 75.030 54.560 75.260 54.875 ;
        RECT 74.950 54.300 75.310 54.560 ;
        RECT 75.030 53.950 75.260 54.300 ;
        RECT 74.950 53.690 75.310 53.950 ;
        RECT 75.030 50.440 75.260 53.690 ;
        RECT 75.510 52.435 75.740 55.440 ;
        RECT 75.990 55.130 76.220 55.440 ;
        RECT 75.925 54.870 76.285 55.130 ;
        RECT 75.990 54.565 76.220 54.870 ;
        RECT 75.925 54.305 76.285 54.565 ;
        RECT 75.990 53.955 76.220 54.305 ;
        RECT 75.925 53.695 76.285 53.955 ;
        RECT 75.445 52.175 75.805 52.435 ;
        RECT 75.510 51.720 75.740 52.175 ;
        RECT 75.445 51.460 75.805 51.720 ;
        RECT 75.510 51.040 75.740 51.460 ;
        RECT 75.445 50.780 75.805 51.040 ;
        RECT 75.510 50.440 75.740 50.780 ;
        RECT 75.990 50.440 76.220 53.695 ;
        RECT 76.470 52.435 76.700 55.440 ;
        RECT 76.950 55.130 77.180 55.440 ;
        RECT 76.885 54.870 77.245 55.130 ;
        RECT 76.950 54.565 77.180 54.870 ;
        RECT 76.885 54.305 77.245 54.565 ;
        RECT 76.950 53.955 77.180 54.305 ;
        RECT 76.885 53.695 77.245 53.955 ;
        RECT 76.405 52.175 76.765 52.435 ;
        RECT 76.470 51.720 76.700 52.175 ;
        RECT 76.405 51.460 76.765 51.720 ;
        RECT 76.470 51.040 76.700 51.460 ;
        RECT 76.405 50.780 76.765 51.040 ;
        RECT 76.470 50.440 76.700 50.780 ;
        RECT 76.950 50.440 77.180 53.695 ;
        RECT 77.430 52.435 77.660 55.440 ;
        RECT 77.910 55.130 78.140 55.440 ;
        RECT 77.845 54.870 78.205 55.130 ;
        RECT 77.910 54.565 78.140 54.870 ;
        RECT 77.845 54.305 78.205 54.565 ;
        RECT 77.910 53.955 78.140 54.305 ;
        RECT 77.845 53.695 78.205 53.955 ;
        RECT 77.365 52.175 77.725 52.435 ;
        RECT 77.430 51.720 77.660 52.175 ;
        RECT 77.365 51.460 77.725 51.720 ;
        RECT 77.430 51.040 77.660 51.460 ;
        RECT 77.365 50.780 77.725 51.040 ;
        RECT 77.430 50.440 77.660 50.780 ;
        RECT 77.910 50.440 78.140 53.695 ;
        RECT 78.390 52.435 78.620 55.440 ;
        RECT 78.870 55.130 79.100 55.440 ;
        RECT 78.805 54.870 79.165 55.130 ;
        RECT 78.870 54.565 79.100 54.870 ;
        RECT 78.805 54.305 79.165 54.565 ;
        RECT 78.870 53.955 79.100 54.305 ;
        RECT 78.805 53.695 79.165 53.955 ;
        RECT 78.325 52.175 78.685 52.435 ;
        RECT 78.390 51.720 78.620 52.175 ;
        RECT 78.325 51.460 78.685 51.720 ;
        RECT 78.390 51.040 78.620 51.460 ;
        RECT 78.325 50.780 78.685 51.040 ;
        RECT 78.390 50.440 78.620 50.780 ;
        RECT 78.870 50.440 79.100 53.695 ;
        RECT 79.350 52.435 79.580 55.440 ;
        RECT 79.830 55.130 80.060 55.440 ;
        RECT 79.765 54.870 80.125 55.130 ;
        RECT 79.830 54.565 80.060 54.870 ;
        RECT 79.770 54.305 80.130 54.565 ;
        RECT 79.830 53.955 80.060 54.305 ;
        RECT 79.765 53.695 80.125 53.955 ;
        RECT 79.285 52.175 79.645 52.435 ;
        RECT 79.350 51.720 79.580 52.175 ;
        RECT 79.285 51.460 79.645 51.720 ;
        RECT 79.350 51.040 79.580 51.460 ;
        RECT 79.285 50.780 79.645 51.040 ;
        RECT 79.350 50.440 79.580 50.780 ;
        RECT 79.830 50.440 80.060 53.695 ;
        RECT 80.310 52.435 80.540 55.440 ;
        RECT 80.790 55.130 81.020 55.440 ;
        RECT 80.725 54.870 81.085 55.130 ;
        RECT 80.790 54.565 81.020 54.870 ;
        RECT 80.725 54.305 81.085 54.565 ;
        RECT 80.790 53.955 81.020 54.305 ;
        RECT 80.720 53.695 81.080 53.955 ;
        RECT 80.250 52.175 80.610 52.435 ;
        RECT 80.310 51.720 80.540 52.175 ;
        RECT 80.245 51.460 80.605 51.720 ;
        RECT 80.310 51.040 80.540 51.460 ;
        RECT 80.250 50.780 80.610 51.040 ;
        RECT 80.310 50.440 80.540 50.780 ;
        RECT 80.790 50.440 81.020 53.695 ;
        RECT 81.230 50.300 81.530 55.580 ;
        RECT 75.150 50.250 81.530 50.300 ;
        RECT 75.145 50.080 81.530 50.250 ;
        RECT 75.150 50.000 81.530 50.080 ;
        RECT 84.505 55.580 90.910 55.880 ;
        RECT 84.505 50.300 84.805 55.580 ;
        RECT 85.030 55.135 85.260 55.440 ;
        RECT 84.950 54.875 85.310 55.135 ;
        RECT 85.030 54.560 85.260 54.875 ;
        RECT 84.950 54.300 85.310 54.560 ;
        RECT 85.030 53.950 85.260 54.300 ;
        RECT 84.950 53.690 85.310 53.950 ;
        RECT 85.030 50.440 85.260 53.690 ;
        RECT 85.510 52.435 85.740 55.440 ;
        RECT 85.990 55.130 86.220 55.440 ;
        RECT 85.925 54.870 86.285 55.130 ;
        RECT 85.990 54.565 86.220 54.870 ;
        RECT 85.925 54.305 86.285 54.565 ;
        RECT 85.990 53.955 86.220 54.305 ;
        RECT 85.925 53.695 86.285 53.955 ;
        RECT 85.445 52.175 85.805 52.435 ;
        RECT 85.510 51.720 85.740 52.175 ;
        RECT 85.445 51.460 85.805 51.720 ;
        RECT 85.510 51.040 85.740 51.460 ;
        RECT 85.445 50.780 85.805 51.040 ;
        RECT 85.510 50.440 85.740 50.780 ;
        RECT 85.990 50.440 86.220 53.695 ;
        RECT 86.470 52.435 86.700 55.440 ;
        RECT 86.950 55.130 87.180 55.440 ;
        RECT 86.885 54.870 87.245 55.130 ;
        RECT 86.950 54.565 87.180 54.870 ;
        RECT 86.885 54.305 87.245 54.565 ;
        RECT 86.950 53.955 87.180 54.305 ;
        RECT 86.885 53.695 87.245 53.955 ;
        RECT 86.405 52.175 86.765 52.435 ;
        RECT 86.470 51.720 86.700 52.175 ;
        RECT 86.405 51.460 86.765 51.720 ;
        RECT 86.470 51.040 86.700 51.460 ;
        RECT 86.405 50.780 86.765 51.040 ;
        RECT 86.470 50.440 86.700 50.780 ;
        RECT 86.950 50.440 87.180 53.695 ;
        RECT 87.430 52.435 87.660 55.440 ;
        RECT 87.910 55.130 88.140 55.440 ;
        RECT 87.845 54.870 88.205 55.130 ;
        RECT 87.910 54.565 88.140 54.870 ;
        RECT 87.845 54.305 88.205 54.565 ;
        RECT 87.910 53.955 88.140 54.305 ;
        RECT 87.845 53.695 88.205 53.955 ;
        RECT 87.365 52.175 87.725 52.435 ;
        RECT 87.430 51.720 87.660 52.175 ;
        RECT 87.365 51.460 87.725 51.720 ;
        RECT 87.430 51.040 87.660 51.460 ;
        RECT 87.365 50.780 87.725 51.040 ;
        RECT 87.430 50.440 87.660 50.780 ;
        RECT 87.910 50.440 88.140 53.695 ;
        RECT 88.390 52.435 88.620 55.440 ;
        RECT 88.870 55.130 89.100 55.440 ;
        RECT 88.805 54.870 89.165 55.130 ;
        RECT 88.870 54.565 89.100 54.870 ;
        RECT 88.805 54.305 89.165 54.565 ;
        RECT 88.870 53.955 89.100 54.305 ;
        RECT 88.805 53.695 89.165 53.955 ;
        RECT 88.325 52.175 88.685 52.435 ;
        RECT 88.390 51.720 88.620 52.175 ;
        RECT 88.325 51.460 88.685 51.720 ;
        RECT 88.390 51.040 88.620 51.460 ;
        RECT 88.325 50.780 88.685 51.040 ;
        RECT 88.390 50.440 88.620 50.780 ;
        RECT 88.870 50.440 89.100 53.695 ;
        RECT 89.350 52.435 89.580 55.440 ;
        RECT 89.830 55.130 90.060 55.440 ;
        RECT 89.765 54.870 90.125 55.130 ;
        RECT 89.830 54.565 90.060 54.870 ;
        RECT 89.770 54.305 90.130 54.565 ;
        RECT 89.830 53.955 90.060 54.305 ;
        RECT 89.765 53.695 90.125 53.955 ;
        RECT 89.285 52.175 89.645 52.435 ;
        RECT 89.350 51.720 89.580 52.175 ;
        RECT 89.285 51.460 89.645 51.720 ;
        RECT 89.350 51.040 89.580 51.460 ;
        RECT 89.285 50.780 89.645 51.040 ;
        RECT 89.350 50.440 89.580 50.780 ;
        RECT 89.830 50.440 90.060 53.695 ;
        RECT 90.310 52.435 90.540 55.440 ;
        RECT 90.790 55.130 91.020 55.440 ;
        RECT 90.725 54.870 91.085 55.130 ;
        RECT 90.790 54.565 91.020 54.870 ;
        RECT 90.725 54.305 91.085 54.565 ;
        RECT 90.790 53.955 91.020 54.305 ;
        RECT 90.720 53.695 91.080 53.955 ;
        RECT 90.250 52.175 90.610 52.435 ;
        RECT 90.310 51.720 90.540 52.175 ;
        RECT 90.245 51.460 90.605 51.720 ;
        RECT 90.310 51.040 90.540 51.460 ;
        RECT 90.250 50.780 90.610 51.040 ;
        RECT 90.310 50.440 90.540 50.780 ;
        RECT 90.790 50.440 91.020 53.695 ;
        RECT 84.505 50.000 90.915 50.300 ;
        RECT 84.505 49.300 84.805 50.000 ;
        RECT 66.980 49.000 84.805 49.300 ;
        RECT 66.980 47.880 69.160 49.000 ;
        RECT 87.460 48.400 89.610 49.520 ;
        RECT 95.820 47.880 97.980 56.575 ;
        RECT 102.045 53.270 104.090 58.960 ;
        RECT 66.980 47.580 80.910 47.880 ;
        RECT 85.120 47.580 97.980 47.880 ;
        RECT 60.890 40.850 62.935 46.540 ;
        RECT 66.980 41.300 69.160 47.580 ;
        RECT 73.910 42.300 74.210 47.580 ;
        RECT 75.030 47.135 75.260 47.440 ;
        RECT 74.950 46.875 75.310 47.135 ;
        RECT 75.030 46.560 75.260 46.875 ;
        RECT 74.950 46.300 75.310 46.560 ;
        RECT 75.030 45.950 75.260 46.300 ;
        RECT 74.950 45.690 75.310 45.950 ;
        RECT 75.030 42.440 75.260 45.690 ;
        RECT 75.510 44.435 75.740 47.440 ;
        RECT 75.990 47.130 76.220 47.440 ;
        RECT 75.925 46.870 76.285 47.130 ;
        RECT 75.990 46.565 76.220 46.870 ;
        RECT 75.925 46.305 76.285 46.565 ;
        RECT 75.990 45.955 76.220 46.305 ;
        RECT 75.925 45.695 76.285 45.955 ;
        RECT 75.445 44.175 75.805 44.435 ;
        RECT 75.510 43.720 75.740 44.175 ;
        RECT 75.445 43.460 75.805 43.720 ;
        RECT 75.510 43.040 75.740 43.460 ;
        RECT 75.445 42.780 75.805 43.040 ;
        RECT 75.510 42.440 75.740 42.780 ;
        RECT 75.990 42.440 76.220 45.695 ;
        RECT 76.470 44.435 76.700 47.440 ;
        RECT 76.950 47.130 77.180 47.440 ;
        RECT 76.885 46.870 77.245 47.130 ;
        RECT 76.950 46.565 77.180 46.870 ;
        RECT 76.885 46.305 77.245 46.565 ;
        RECT 76.950 45.955 77.180 46.305 ;
        RECT 76.885 45.695 77.245 45.955 ;
        RECT 76.405 44.175 76.765 44.435 ;
        RECT 76.470 43.720 76.700 44.175 ;
        RECT 76.405 43.460 76.765 43.720 ;
        RECT 76.470 43.040 76.700 43.460 ;
        RECT 76.405 42.780 76.765 43.040 ;
        RECT 76.470 42.440 76.700 42.780 ;
        RECT 76.950 42.440 77.180 45.695 ;
        RECT 77.430 44.435 77.660 47.440 ;
        RECT 77.910 47.130 78.140 47.440 ;
        RECT 77.845 46.870 78.205 47.130 ;
        RECT 77.910 46.565 78.140 46.870 ;
        RECT 77.845 46.305 78.205 46.565 ;
        RECT 77.910 45.955 78.140 46.305 ;
        RECT 77.845 45.695 78.205 45.955 ;
        RECT 77.365 44.175 77.725 44.435 ;
        RECT 77.430 43.720 77.660 44.175 ;
        RECT 77.365 43.460 77.725 43.720 ;
        RECT 77.430 43.040 77.660 43.460 ;
        RECT 77.365 42.780 77.725 43.040 ;
        RECT 77.430 42.440 77.660 42.780 ;
        RECT 77.910 42.440 78.140 45.695 ;
        RECT 78.390 44.435 78.620 47.440 ;
        RECT 78.870 47.130 79.100 47.440 ;
        RECT 78.805 46.870 79.165 47.130 ;
        RECT 78.870 46.565 79.100 46.870 ;
        RECT 78.805 46.305 79.165 46.565 ;
        RECT 78.870 45.955 79.100 46.305 ;
        RECT 78.805 45.695 79.165 45.955 ;
        RECT 78.325 44.175 78.685 44.435 ;
        RECT 78.390 43.720 78.620 44.175 ;
        RECT 78.325 43.460 78.685 43.720 ;
        RECT 78.390 43.040 78.620 43.460 ;
        RECT 78.325 42.780 78.685 43.040 ;
        RECT 78.390 42.440 78.620 42.780 ;
        RECT 78.870 42.440 79.100 45.695 ;
        RECT 79.350 44.435 79.580 47.440 ;
        RECT 79.830 47.130 80.060 47.440 ;
        RECT 79.765 46.870 80.125 47.130 ;
        RECT 79.830 46.565 80.060 46.870 ;
        RECT 79.770 46.305 80.130 46.565 ;
        RECT 79.830 45.955 80.060 46.305 ;
        RECT 79.765 45.695 80.125 45.955 ;
        RECT 79.285 44.175 79.645 44.435 ;
        RECT 79.350 43.720 79.580 44.175 ;
        RECT 79.285 43.460 79.645 43.720 ;
        RECT 79.350 43.040 79.580 43.460 ;
        RECT 79.285 42.780 79.645 43.040 ;
        RECT 79.350 42.440 79.580 42.780 ;
        RECT 79.830 42.440 80.060 45.695 ;
        RECT 80.310 44.435 80.540 47.440 ;
        RECT 80.790 47.130 81.020 47.440 ;
        RECT 85.030 47.135 85.260 47.440 ;
        RECT 80.725 46.870 81.085 47.130 ;
        RECT 84.950 46.875 85.310 47.135 ;
        RECT 80.790 46.565 81.020 46.870 ;
        RECT 80.725 46.305 81.085 46.565 ;
        RECT 85.030 46.560 85.260 46.875 ;
        RECT 80.790 45.955 81.020 46.305 ;
        RECT 84.950 46.300 85.310 46.560 ;
        RECT 80.720 45.695 81.080 45.955 ;
        RECT 85.030 45.950 85.260 46.300 ;
        RECT 80.250 44.175 80.610 44.435 ;
        RECT 80.310 43.720 80.540 44.175 ;
        RECT 80.245 43.460 80.605 43.720 ;
        RECT 80.310 43.040 80.540 43.460 ;
        RECT 80.250 42.780 80.610 43.040 ;
        RECT 80.310 42.440 80.540 42.780 ;
        RECT 80.790 42.440 81.020 45.695 ;
        RECT 84.950 45.690 85.310 45.950 ;
        RECT 85.030 42.440 85.260 45.690 ;
        RECT 85.510 44.435 85.740 47.440 ;
        RECT 85.990 47.130 86.220 47.440 ;
        RECT 85.925 46.870 86.285 47.130 ;
        RECT 85.990 46.565 86.220 46.870 ;
        RECT 85.925 46.305 86.285 46.565 ;
        RECT 85.990 45.955 86.220 46.305 ;
        RECT 85.925 45.695 86.285 45.955 ;
        RECT 85.445 44.175 85.805 44.435 ;
        RECT 85.510 43.720 85.740 44.175 ;
        RECT 85.445 43.460 85.805 43.720 ;
        RECT 85.510 43.040 85.740 43.460 ;
        RECT 85.445 42.780 85.805 43.040 ;
        RECT 85.510 42.440 85.740 42.780 ;
        RECT 85.990 42.440 86.220 45.695 ;
        RECT 86.470 44.435 86.700 47.440 ;
        RECT 86.950 47.130 87.180 47.440 ;
        RECT 86.885 46.870 87.245 47.130 ;
        RECT 86.950 46.565 87.180 46.870 ;
        RECT 86.885 46.305 87.245 46.565 ;
        RECT 86.950 45.955 87.180 46.305 ;
        RECT 86.885 45.695 87.245 45.955 ;
        RECT 86.405 44.175 86.765 44.435 ;
        RECT 86.470 43.720 86.700 44.175 ;
        RECT 86.405 43.460 86.765 43.720 ;
        RECT 86.470 43.040 86.700 43.460 ;
        RECT 86.405 42.780 86.765 43.040 ;
        RECT 86.470 42.440 86.700 42.780 ;
        RECT 86.950 42.440 87.180 45.695 ;
        RECT 87.430 44.435 87.660 47.440 ;
        RECT 87.910 47.130 88.140 47.440 ;
        RECT 87.845 46.870 88.205 47.130 ;
        RECT 87.910 46.565 88.140 46.870 ;
        RECT 87.845 46.305 88.205 46.565 ;
        RECT 87.910 45.955 88.140 46.305 ;
        RECT 87.845 45.695 88.205 45.955 ;
        RECT 87.365 44.175 87.725 44.435 ;
        RECT 87.430 43.720 87.660 44.175 ;
        RECT 87.365 43.460 87.725 43.720 ;
        RECT 87.430 43.040 87.660 43.460 ;
        RECT 87.365 42.780 87.725 43.040 ;
        RECT 87.430 42.440 87.660 42.780 ;
        RECT 87.910 42.440 88.140 45.695 ;
        RECT 88.390 44.435 88.620 47.440 ;
        RECT 88.870 47.130 89.100 47.440 ;
        RECT 88.805 46.870 89.165 47.130 ;
        RECT 88.870 46.565 89.100 46.870 ;
        RECT 88.805 46.305 89.165 46.565 ;
        RECT 88.870 45.955 89.100 46.305 ;
        RECT 88.805 45.695 89.165 45.955 ;
        RECT 88.325 44.175 88.685 44.435 ;
        RECT 88.390 43.720 88.620 44.175 ;
        RECT 88.325 43.460 88.685 43.720 ;
        RECT 88.390 43.040 88.620 43.460 ;
        RECT 88.325 42.780 88.685 43.040 ;
        RECT 88.390 42.440 88.620 42.780 ;
        RECT 88.870 42.440 89.100 45.695 ;
        RECT 89.350 44.435 89.580 47.440 ;
        RECT 89.830 47.130 90.060 47.440 ;
        RECT 89.765 46.870 90.125 47.130 ;
        RECT 89.830 46.565 90.060 46.870 ;
        RECT 89.770 46.305 90.130 46.565 ;
        RECT 89.830 45.955 90.060 46.305 ;
        RECT 89.765 45.695 90.125 45.955 ;
        RECT 89.285 44.175 89.645 44.435 ;
        RECT 89.350 43.720 89.580 44.175 ;
        RECT 89.285 43.460 89.645 43.720 ;
        RECT 89.350 43.040 89.580 43.460 ;
        RECT 89.285 42.780 89.645 43.040 ;
        RECT 89.350 42.440 89.580 42.780 ;
        RECT 89.830 42.440 90.060 45.695 ;
        RECT 90.310 44.435 90.540 47.440 ;
        RECT 90.790 47.130 91.020 47.440 ;
        RECT 90.725 46.870 91.085 47.130 ;
        RECT 90.790 46.565 91.020 46.870 ;
        RECT 90.725 46.305 91.085 46.565 ;
        RECT 90.790 45.955 91.020 46.305 ;
        RECT 90.720 45.695 91.080 45.955 ;
        RECT 90.250 44.175 90.610 44.435 ;
        RECT 90.310 43.720 90.540 44.175 ;
        RECT 90.245 43.460 90.605 43.720 ;
        RECT 90.310 43.040 90.540 43.460 ;
        RECT 90.250 42.780 90.610 43.040 ;
        RECT 90.310 42.440 90.540 42.780 ;
        RECT 90.790 42.440 91.020 45.695 ;
        RECT 91.835 42.300 92.135 47.580 ;
        RECT 73.910 42.000 80.910 42.300 ;
        RECT 85.135 42.000 92.135 42.300 ;
        RECT 95.820 41.890 97.980 47.580 ;
        RECT 102.045 47.060 104.090 52.750 ;
        RECT 93.550 41.590 97.980 41.890 ;
        RECT 66.980 41.000 73.210 41.300 ;
        RECT 66.980 40.830 69.160 41.000 ;
        RECT 42.660 35.340 43.590 35.580 ;
        RECT 42.660 34.600 43.670 35.340 ;
        RECT 55.290 34.740 56.220 34.830 ;
        RECT 42.700 34.100 43.670 34.600 ;
        RECT 54.610 33.830 56.860 34.740 ;
        RECT 43.410 27.895 45.455 33.585 ;
        RECT 52.005 27.895 54.050 33.585 ;
        RECT 72.910 33.300 73.210 41.000 ;
        RECT 76.440 40.350 78.590 41.470 ;
        RECT 93.550 40.885 93.850 41.590 ;
        RECT 81.230 40.585 93.850 40.885 ;
        RECT 95.820 40.810 97.980 41.590 ;
        RECT 102.045 40.850 104.090 46.540 ;
        RECT 108.120 46.070 109.420 47.280 ;
        RECT 81.230 39.880 81.530 40.585 ;
        RECT 75.145 39.580 81.530 39.880 ;
        RECT 75.030 39.135 75.260 39.440 ;
        RECT 74.950 38.875 75.310 39.135 ;
        RECT 75.030 38.560 75.260 38.875 ;
        RECT 74.950 38.300 75.310 38.560 ;
        RECT 75.030 37.950 75.260 38.300 ;
        RECT 74.950 37.690 75.310 37.950 ;
        RECT 75.030 34.440 75.260 37.690 ;
        RECT 75.510 36.435 75.740 39.440 ;
        RECT 75.990 39.130 76.220 39.440 ;
        RECT 75.925 38.870 76.285 39.130 ;
        RECT 75.990 38.565 76.220 38.870 ;
        RECT 75.925 38.305 76.285 38.565 ;
        RECT 75.990 37.955 76.220 38.305 ;
        RECT 75.925 37.695 76.285 37.955 ;
        RECT 75.445 36.175 75.805 36.435 ;
        RECT 75.510 35.720 75.740 36.175 ;
        RECT 75.445 35.460 75.805 35.720 ;
        RECT 75.510 35.040 75.740 35.460 ;
        RECT 75.445 34.780 75.805 35.040 ;
        RECT 75.510 34.440 75.740 34.780 ;
        RECT 75.990 34.440 76.220 37.695 ;
        RECT 76.470 36.435 76.700 39.440 ;
        RECT 76.950 39.130 77.180 39.440 ;
        RECT 76.885 38.870 77.245 39.130 ;
        RECT 76.950 38.565 77.180 38.870 ;
        RECT 76.885 38.305 77.245 38.565 ;
        RECT 76.950 37.955 77.180 38.305 ;
        RECT 76.885 37.695 77.245 37.955 ;
        RECT 76.405 36.175 76.765 36.435 ;
        RECT 76.470 35.720 76.700 36.175 ;
        RECT 76.405 35.460 76.765 35.720 ;
        RECT 76.470 35.040 76.700 35.460 ;
        RECT 76.405 34.780 76.765 35.040 ;
        RECT 76.470 34.440 76.700 34.780 ;
        RECT 76.950 34.440 77.180 37.695 ;
        RECT 77.430 36.435 77.660 39.440 ;
        RECT 77.910 39.130 78.140 39.440 ;
        RECT 77.845 38.870 78.205 39.130 ;
        RECT 77.910 38.565 78.140 38.870 ;
        RECT 77.845 38.305 78.205 38.565 ;
        RECT 77.910 37.955 78.140 38.305 ;
        RECT 77.845 37.695 78.205 37.955 ;
        RECT 77.365 36.175 77.725 36.435 ;
        RECT 77.430 35.720 77.660 36.175 ;
        RECT 77.365 35.460 77.725 35.720 ;
        RECT 77.430 35.040 77.660 35.460 ;
        RECT 77.365 34.780 77.725 35.040 ;
        RECT 77.430 34.440 77.660 34.780 ;
        RECT 77.910 34.440 78.140 37.695 ;
        RECT 78.390 36.435 78.620 39.440 ;
        RECT 78.870 39.130 79.100 39.440 ;
        RECT 78.805 38.870 79.165 39.130 ;
        RECT 78.870 38.565 79.100 38.870 ;
        RECT 78.805 38.305 79.165 38.565 ;
        RECT 78.870 37.955 79.100 38.305 ;
        RECT 78.805 37.695 79.165 37.955 ;
        RECT 78.325 36.175 78.685 36.435 ;
        RECT 78.390 35.720 78.620 36.175 ;
        RECT 78.325 35.460 78.685 35.720 ;
        RECT 78.390 35.040 78.620 35.460 ;
        RECT 78.325 34.780 78.685 35.040 ;
        RECT 78.390 34.440 78.620 34.780 ;
        RECT 78.870 34.440 79.100 37.695 ;
        RECT 79.350 36.435 79.580 39.440 ;
        RECT 79.830 39.130 80.060 39.440 ;
        RECT 79.765 38.870 80.125 39.130 ;
        RECT 79.830 38.565 80.060 38.870 ;
        RECT 79.770 38.305 80.130 38.565 ;
        RECT 79.830 37.955 80.060 38.305 ;
        RECT 79.765 37.695 80.125 37.955 ;
        RECT 79.285 36.175 79.645 36.435 ;
        RECT 79.350 35.720 79.580 36.175 ;
        RECT 79.285 35.460 79.645 35.720 ;
        RECT 79.350 35.040 79.580 35.460 ;
        RECT 79.285 34.780 79.645 35.040 ;
        RECT 79.350 34.440 79.580 34.780 ;
        RECT 79.830 34.440 80.060 37.695 ;
        RECT 80.310 36.435 80.540 39.440 ;
        RECT 80.790 39.130 81.020 39.440 ;
        RECT 80.725 38.870 81.085 39.130 ;
        RECT 80.790 38.565 81.020 38.870 ;
        RECT 80.725 38.305 81.085 38.565 ;
        RECT 80.790 37.955 81.020 38.305 ;
        RECT 80.720 37.695 81.080 37.955 ;
        RECT 80.250 36.175 80.610 36.435 ;
        RECT 80.310 35.720 80.540 36.175 ;
        RECT 80.245 35.460 80.605 35.720 ;
        RECT 80.310 35.040 80.540 35.460 ;
        RECT 80.250 34.780 80.610 35.040 ;
        RECT 80.310 34.440 80.540 34.780 ;
        RECT 80.790 34.440 81.020 37.695 ;
        RECT 81.230 34.300 81.530 39.580 ;
        RECT 75.150 34.250 81.530 34.300 ;
        RECT 75.145 34.080 81.530 34.250 ;
        RECT 75.150 34.000 81.530 34.080 ;
        RECT 84.490 39.580 90.910 39.880 ;
        RECT 84.490 34.300 84.790 39.580 ;
        RECT 85.030 39.135 85.260 39.440 ;
        RECT 84.950 38.875 85.310 39.135 ;
        RECT 85.030 38.560 85.260 38.875 ;
        RECT 84.950 38.300 85.310 38.560 ;
        RECT 85.030 37.950 85.260 38.300 ;
        RECT 84.950 37.690 85.310 37.950 ;
        RECT 85.030 34.440 85.260 37.690 ;
        RECT 85.510 36.435 85.740 39.440 ;
        RECT 85.990 39.130 86.220 39.440 ;
        RECT 85.925 38.870 86.285 39.130 ;
        RECT 85.990 38.565 86.220 38.870 ;
        RECT 85.925 38.305 86.285 38.565 ;
        RECT 85.990 37.955 86.220 38.305 ;
        RECT 85.925 37.695 86.285 37.955 ;
        RECT 85.445 36.175 85.805 36.435 ;
        RECT 85.510 35.720 85.740 36.175 ;
        RECT 85.445 35.460 85.805 35.720 ;
        RECT 85.510 35.040 85.740 35.460 ;
        RECT 85.445 34.780 85.805 35.040 ;
        RECT 85.510 34.440 85.740 34.780 ;
        RECT 85.990 34.440 86.220 37.695 ;
        RECT 86.470 36.435 86.700 39.440 ;
        RECT 86.950 39.130 87.180 39.440 ;
        RECT 86.885 38.870 87.245 39.130 ;
        RECT 86.950 38.565 87.180 38.870 ;
        RECT 86.885 38.305 87.245 38.565 ;
        RECT 86.950 37.955 87.180 38.305 ;
        RECT 86.885 37.695 87.245 37.955 ;
        RECT 86.405 36.175 86.765 36.435 ;
        RECT 86.470 35.720 86.700 36.175 ;
        RECT 86.405 35.460 86.765 35.720 ;
        RECT 86.470 35.040 86.700 35.460 ;
        RECT 86.405 34.780 86.765 35.040 ;
        RECT 86.470 34.440 86.700 34.780 ;
        RECT 86.950 34.440 87.180 37.695 ;
        RECT 87.430 36.435 87.660 39.440 ;
        RECT 87.910 39.130 88.140 39.440 ;
        RECT 87.845 38.870 88.205 39.130 ;
        RECT 87.910 38.565 88.140 38.870 ;
        RECT 87.845 38.305 88.205 38.565 ;
        RECT 87.910 37.955 88.140 38.305 ;
        RECT 87.845 37.695 88.205 37.955 ;
        RECT 87.365 36.175 87.725 36.435 ;
        RECT 87.430 35.720 87.660 36.175 ;
        RECT 87.365 35.460 87.725 35.720 ;
        RECT 87.430 35.040 87.660 35.460 ;
        RECT 87.365 34.780 87.725 35.040 ;
        RECT 87.430 34.440 87.660 34.780 ;
        RECT 87.910 34.440 88.140 37.695 ;
        RECT 88.390 36.435 88.620 39.440 ;
        RECT 88.870 39.130 89.100 39.440 ;
        RECT 88.805 38.870 89.165 39.130 ;
        RECT 88.870 38.565 89.100 38.870 ;
        RECT 88.805 38.305 89.165 38.565 ;
        RECT 88.870 37.955 89.100 38.305 ;
        RECT 88.805 37.695 89.165 37.955 ;
        RECT 88.325 36.175 88.685 36.435 ;
        RECT 88.390 35.720 88.620 36.175 ;
        RECT 88.325 35.460 88.685 35.720 ;
        RECT 88.390 35.040 88.620 35.460 ;
        RECT 88.325 34.780 88.685 35.040 ;
        RECT 88.390 34.440 88.620 34.780 ;
        RECT 88.870 34.440 89.100 37.695 ;
        RECT 89.350 36.435 89.580 39.440 ;
        RECT 89.830 39.130 90.060 39.440 ;
        RECT 89.765 38.870 90.125 39.130 ;
        RECT 89.830 38.565 90.060 38.870 ;
        RECT 89.770 38.305 90.130 38.565 ;
        RECT 89.830 37.955 90.060 38.305 ;
        RECT 89.765 37.695 90.125 37.955 ;
        RECT 89.285 36.175 89.645 36.435 ;
        RECT 89.350 35.720 89.580 36.175 ;
        RECT 89.285 35.460 89.645 35.720 ;
        RECT 89.350 35.040 89.580 35.460 ;
        RECT 89.285 34.780 89.645 35.040 ;
        RECT 89.350 34.440 89.580 34.780 ;
        RECT 89.830 34.440 90.060 37.695 ;
        RECT 90.310 36.435 90.540 39.440 ;
        RECT 90.790 39.130 91.020 39.440 ;
        RECT 90.725 38.870 91.085 39.130 ;
        RECT 90.790 38.565 91.020 38.870 ;
        RECT 90.725 38.305 91.085 38.565 ;
        RECT 90.790 37.955 91.020 38.305 ;
        RECT 90.720 37.695 91.080 37.955 ;
        RECT 90.250 36.175 90.610 36.435 ;
        RECT 90.310 35.720 90.540 36.175 ;
        RECT 90.245 35.460 90.605 35.720 ;
        RECT 90.310 35.040 90.540 35.460 ;
        RECT 90.250 34.780 90.610 35.040 ;
        RECT 90.310 34.440 90.540 34.780 ;
        RECT 90.790 34.440 91.020 37.695 ;
        RECT 84.490 34.000 90.915 34.300 ;
        RECT 84.490 33.300 84.790 34.000 ;
        RECT 72.910 33.000 84.790 33.300 ;
        RECT 108.100 32.230 109.400 33.440 ;
        RECT 57.130 31.160 58.060 31.230 ;
        RECT 56.750 30.250 58.060 31.160 ;
        RECT 56.750 29.950 58.050 30.250 ;
        RECT 42.700 26.970 43.670 27.350 ;
        RECT 42.670 26.110 43.670 26.970 ;
        RECT 56.220 26.230 57.390 27.540 ;
        RECT 114.240 27.040 115.170 27.220 ;
        RECT 42.670 25.990 43.600 26.110 ;
        RECT 52.660 25.790 53.020 25.810 ;
        RECT 53.430 25.790 53.790 25.810 ;
        RECT 54.210 25.790 54.570 25.810 ;
        RECT 60.660 25.790 61.020 25.810 ;
        RECT 61.430 25.790 61.790 25.810 ;
        RECT 62.210 25.790 62.570 25.810 ;
        RECT 68.660 25.790 69.020 25.810 ;
        RECT 69.430 25.790 69.790 25.810 ;
        RECT 70.210 25.790 70.570 25.810 ;
        RECT 76.660 25.790 77.020 25.810 ;
        RECT 77.430 25.790 77.790 25.810 ;
        RECT 78.210 25.790 78.570 25.810 ;
        RECT 52.000 19.510 52.300 25.710 ;
        RECT 52.440 25.560 57.440 25.790 ;
        RECT 52.660 25.550 53.020 25.560 ;
        RECT 53.430 25.550 53.790 25.560 ;
        RECT 54.210 25.550 54.570 25.560 ;
        RECT 55.150 25.000 55.510 25.015 ;
        RECT 56.005 25.000 56.365 25.015 ;
        RECT 56.810 25.000 57.170 25.010 ;
        RECT 52.440 24.770 57.440 25.000 ;
        RECT 55.150 24.755 55.510 24.770 ;
        RECT 56.005 24.755 56.365 24.770 ;
        RECT 56.810 24.750 57.170 24.770 ;
        RECT 52.660 24.210 53.020 24.225 ;
        RECT 53.430 24.210 53.790 24.225 ;
        RECT 54.210 24.210 54.570 24.225 ;
        RECT 52.440 23.980 57.440 24.210 ;
        RECT 52.660 23.965 53.020 23.980 ;
        RECT 53.430 23.965 53.790 23.980 ;
        RECT 54.210 23.965 54.570 23.980 ;
        RECT 55.150 23.420 55.510 23.435 ;
        RECT 56.005 23.420 56.365 23.435 ;
        RECT 56.810 23.420 57.170 23.440 ;
        RECT 52.440 23.190 57.440 23.420 ;
        RECT 55.150 23.175 55.510 23.190 ;
        RECT 56.005 23.175 56.365 23.190 ;
        RECT 56.810 23.180 57.170 23.190 ;
        RECT 52.660 22.630 53.020 22.645 ;
        RECT 53.430 22.630 53.790 22.645 ;
        RECT 54.210 22.630 54.570 22.645 ;
        RECT 52.440 22.400 57.440 22.630 ;
        RECT 52.660 22.385 53.020 22.400 ;
        RECT 53.430 22.385 53.790 22.400 ;
        RECT 54.210 22.385 54.570 22.400 ;
        RECT 55.150 21.840 55.510 21.855 ;
        RECT 56.005 21.840 56.365 21.855 ;
        RECT 56.810 21.840 57.170 21.855 ;
        RECT 52.440 21.610 57.440 21.840 ;
        RECT 55.150 21.595 55.510 21.610 ;
        RECT 56.005 21.595 56.365 21.610 ;
        RECT 56.810 21.595 57.170 21.610 ;
        RECT 52.660 21.050 53.020 21.065 ;
        RECT 53.430 21.050 53.790 21.065 ;
        RECT 54.210 21.050 54.570 21.065 ;
        RECT 52.440 20.820 57.440 21.050 ;
        RECT 52.660 20.805 53.020 20.820 ;
        RECT 53.430 20.805 53.790 20.820 ;
        RECT 54.210 20.805 54.570 20.820 ;
        RECT 55.150 20.260 55.510 20.270 ;
        RECT 56.010 20.260 56.370 20.270 ;
        RECT 56.810 20.260 57.170 20.270 ;
        RECT 52.440 20.030 57.440 20.260 ;
        RECT 55.150 20.010 55.510 20.030 ;
        RECT 56.010 20.010 56.370 20.030 ;
        RECT 56.810 20.010 57.170 20.030 ;
        RECT 57.580 19.510 57.880 25.710 ;
        RECT 60.000 19.510 60.300 25.710 ;
        RECT 60.440 25.560 65.440 25.790 ;
        RECT 60.660 25.550 61.020 25.560 ;
        RECT 61.430 25.550 61.790 25.560 ;
        RECT 62.210 25.550 62.570 25.560 ;
        RECT 63.150 25.000 63.510 25.015 ;
        RECT 64.005 25.000 64.365 25.015 ;
        RECT 64.810 25.000 65.170 25.010 ;
        RECT 60.440 24.770 65.440 25.000 ;
        RECT 63.150 24.755 63.510 24.770 ;
        RECT 64.005 24.755 64.365 24.770 ;
        RECT 64.810 24.750 65.170 24.770 ;
        RECT 60.660 24.210 61.020 24.225 ;
        RECT 61.430 24.210 61.790 24.225 ;
        RECT 62.210 24.210 62.570 24.225 ;
        RECT 60.440 23.980 65.440 24.210 ;
        RECT 60.660 23.965 61.020 23.980 ;
        RECT 61.430 23.965 61.790 23.980 ;
        RECT 62.210 23.965 62.570 23.980 ;
        RECT 63.150 23.420 63.510 23.435 ;
        RECT 64.005 23.420 64.365 23.435 ;
        RECT 64.810 23.420 65.170 23.440 ;
        RECT 60.440 23.190 65.440 23.420 ;
        RECT 63.150 23.175 63.510 23.190 ;
        RECT 64.005 23.175 64.365 23.190 ;
        RECT 64.810 23.180 65.170 23.190 ;
        RECT 60.660 22.630 61.020 22.645 ;
        RECT 61.430 22.630 61.790 22.645 ;
        RECT 62.210 22.630 62.570 22.645 ;
        RECT 60.440 22.400 65.440 22.630 ;
        RECT 60.660 22.385 61.020 22.400 ;
        RECT 61.430 22.385 61.790 22.400 ;
        RECT 62.210 22.385 62.570 22.400 ;
        RECT 63.150 21.840 63.510 21.855 ;
        RECT 64.005 21.840 64.365 21.855 ;
        RECT 64.810 21.840 65.170 21.855 ;
        RECT 60.440 21.610 65.440 21.840 ;
        RECT 63.150 21.595 63.510 21.610 ;
        RECT 64.005 21.595 64.365 21.610 ;
        RECT 64.810 21.595 65.170 21.610 ;
        RECT 60.660 21.050 61.020 21.065 ;
        RECT 61.430 21.050 61.790 21.065 ;
        RECT 62.210 21.050 62.570 21.065 ;
        RECT 60.440 20.820 65.440 21.050 ;
        RECT 60.660 20.805 61.020 20.820 ;
        RECT 61.430 20.805 61.790 20.820 ;
        RECT 62.210 20.805 62.570 20.820 ;
        RECT 63.150 20.260 63.510 20.270 ;
        RECT 64.010 20.260 64.370 20.270 ;
        RECT 64.810 20.260 65.170 20.270 ;
        RECT 60.440 20.030 65.440 20.260 ;
        RECT 63.150 20.010 63.510 20.030 ;
        RECT 64.010 20.010 64.370 20.030 ;
        RECT 64.810 20.010 65.170 20.030 ;
        RECT 65.580 19.510 65.880 25.690 ;
        RECT 68.000 19.510 68.300 25.700 ;
        RECT 68.440 25.560 73.440 25.790 ;
        RECT 68.660 25.550 69.020 25.560 ;
        RECT 69.430 25.550 69.790 25.560 ;
        RECT 70.210 25.550 70.570 25.560 ;
        RECT 71.150 25.000 71.510 25.015 ;
        RECT 72.005 25.000 72.365 25.015 ;
        RECT 72.810 25.000 73.170 25.010 ;
        RECT 68.440 24.770 73.440 25.000 ;
        RECT 71.150 24.755 71.510 24.770 ;
        RECT 72.005 24.755 72.365 24.770 ;
        RECT 72.810 24.750 73.170 24.770 ;
        RECT 68.660 24.210 69.020 24.225 ;
        RECT 69.430 24.210 69.790 24.225 ;
        RECT 70.210 24.210 70.570 24.225 ;
        RECT 68.440 23.980 73.440 24.210 ;
        RECT 68.660 23.965 69.020 23.980 ;
        RECT 69.430 23.965 69.790 23.980 ;
        RECT 70.210 23.965 70.570 23.980 ;
        RECT 71.150 23.420 71.510 23.435 ;
        RECT 72.005 23.420 72.365 23.435 ;
        RECT 72.810 23.420 73.170 23.440 ;
        RECT 68.440 23.190 73.440 23.420 ;
        RECT 71.150 23.175 71.510 23.190 ;
        RECT 72.005 23.175 72.365 23.190 ;
        RECT 72.810 23.180 73.170 23.190 ;
        RECT 68.660 22.630 69.020 22.645 ;
        RECT 69.430 22.630 69.790 22.645 ;
        RECT 70.210 22.630 70.570 22.645 ;
        RECT 68.440 22.400 73.440 22.630 ;
        RECT 68.660 22.385 69.020 22.400 ;
        RECT 69.430 22.385 69.790 22.400 ;
        RECT 70.210 22.385 70.570 22.400 ;
        RECT 71.150 21.840 71.510 21.855 ;
        RECT 72.005 21.840 72.365 21.855 ;
        RECT 72.810 21.840 73.170 21.855 ;
        RECT 68.440 21.610 73.440 21.840 ;
        RECT 71.150 21.595 71.510 21.610 ;
        RECT 72.005 21.595 72.365 21.610 ;
        RECT 72.810 21.595 73.170 21.610 ;
        RECT 68.660 21.050 69.020 21.065 ;
        RECT 69.430 21.050 69.790 21.065 ;
        RECT 70.210 21.050 70.570 21.065 ;
        RECT 68.440 20.820 73.440 21.050 ;
        RECT 68.660 20.805 69.020 20.820 ;
        RECT 69.430 20.805 69.790 20.820 ;
        RECT 70.210 20.805 70.570 20.820 ;
        RECT 71.150 20.260 71.510 20.270 ;
        RECT 72.010 20.260 72.370 20.270 ;
        RECT 72.810 20.260 73.170 20.270 ;
        RECT 68.440 20.030 73.440 20.260 ;
        RECT 71.150 20.010 71.510 20.030 ;
        RECT 72.010 20.010 72.370 20.030 ;
        RECT 72.810 20.010 73.170 20.030 ;
        RECT 73.580 19.510 73.880 25.685 ;
        RECT 76.000 19.510 76.300 25.680 ;
        RECT 76.440 25.560 81.440 25.790 ;
        RECT 76.660 25.550 77.020 25.560 ;
        RECT 77.430 25.550 77.790 25.560 ;
        RECT 78.210 25.550 78.570 25.560 ;
        RECT 79.150 25.000 79.510 25.015 ;
        RECT 80.005 25.000 80.365 25.015 ;
        RECT 80.810 25.000 81.170 25.010 ;
        RECT 76.440 24.770 81.440 25.000 ;
        RECT 79.150 24.755 79.510 24.770 ;
        RECT 80.005 24.755 80.365 24.770 ;
        RECT 80.810 24.750 81.170 24.770 ;
        RECT 76.660 24.210 77.020 24.225 ;
        RECT 77.430 24.210 77.790 24.225 ;
        RECT 78.210 24.210 78.570 24.225 ;
        RECT 76.440 23.980 81.440 24.210 ;
        RECT 76.660 23.965 77.020 23.980 ;
        RECT 77.430 23.965 77.790 23.980 ;
        RECT 78.210 23.965 78.570 23.980 ;
        RECT 79.150 23.420 79.510 23.435 ;
        RECT 80.005 23.420 80.365 23.435 ;
        RECT 80.810 23.420 81.170 23.440 ;
        RECT 76.440 23.190 81.440 23.420 ;
        RECT 79.150 23.175 79.510 23.190 ;
        RECT 80.005 23.175 80.365 23.190 ;
        RECT 80.810 23.180 81.170 23.190 ;
        RECT 76.660 22.630 77.020 22.645 ;
        RECT 77.430 22.630 77.790 22.645 ;
        RECT 78.210 22.630 78.570 22.645 ;
        RECT 76.440 22.400 81.440 22.630 ;
        RECT 76.660 22.385 77.020 22.400 ;
        RECT 77.430 22.385 77.790 22.400 ;
        RECT 78.210 22.385 78.570 22.400 ;
        RECT 79.150 21.840 79.510 21.855 ;
        RECT 80.005 21.840 80.365 21.855 ;
        RECT 80.810 21.840 81.170 21.855 ;
        RECT 76.440 21.610 81.440 21.840 ;
        RECT 79.150 21.595 79.510 21.610 ;
        RECT 80.005 21.595 80.365 21.610 ;
        RECT 80.810 21.595 81.170 21.610 ;
        RECT 76.660 21.050 77.020 21.065 ;
        RECT 77.430 21.050 77.790 21.065 ;
        RECT 78.210 21.050 78.570 21.065 ;
        RECT 76.440 20.820 81.440 21.050 ;
        RECT 76.660 20.805 77.020 20.820 ;
        RECT 77.430 20.805 77.790 20.820 ;
        RECT 78.210 20.805 78.570 20.820 ;
        RECT 79.150 20.260 79.510 20.270 ;
        RECT 80.010 20.260 80.370 20.270 ;
        RECT 80.810 20.260 81.170 20.270 ;
        RECT 76.440 20.030 81.440 20.260 ;
        RECT 79.150 20.010 79.510 20.030 ;
        RECT 80.010 20.010 80.370 20.030 ;
        RECT 80.810 20.010 81.170 20.030 ;
        RECT 81.580 19.510 81.880 25.700 ;
        RECT 82.340 25.040 83.510 26.350 ;
        RECT 84.660 25.790 85.020 25.810 ;
        RECT 85.430 25.790 85.790 25.810 ;
        RECT 86.210 25.790 86.570 25.810 ;
        RECT 92.660 25.790 93.020 25.810 ;
        RECT 93.430 25.790 93.790 25.810 ;
        RECT 94.210 25.790 94.570 25.810 ;
        RECT 100.660 25.790 101.020 25.810 ;
        RECT 101.430 25.790 101.790 25.810 ;
        RECT 102.210 25.790 102.570 25.810 ;
        RECT 108.660 25.790 109.020 25.810 ;
        RECT 109.430 25.790 109.790 25.810 ;
        RECT 110.210 25.790 110.570 25.810 ;
        RECT 84.000 19.510 84.300 25.690 ;
        RECT 84.440 25.560 89.440 25.790 ;
        RECT 84.660 25.550 85.020 25.560 ;
        RECT 85.430 25.550 85.790 25.560 ;
        RECT 86.210 25.550 86.570 25.560 ;
        RECT 87.150 25.000 87.510 25.015 ;
        RECT 88.005 25.000 88.365 25.015 ;
        RECT 88.810 25.000 89.170 25.010 ;
        RECT 84.440 24.770 89.440 25.000 ;
        RECT 87.150 24.755 87.510 24.770 ;
        RECT 88.005 24.755 88.365 24.770 ;
        RECT 88.810 24.750 89.170 24.770 ;
        RECT 84.660 24.210 85.020 24.225 ;
        RECT 85.430 24.210 85.790 24.225 ;
        RECT 86.210 24.210 86.570 24.225 ;
        RECT 84.440 23.980 89.440 24.210 ;
        RECT 84.660 23.965 85.020 23.980 ;
        RECT 85.430 23.965 85.790 23.980 ;
        RECT 86.210 23.965 86.570 23.980 ;
        RECT 87.150 23.420 87.510 23.435 ;
        RECT 88.005 23.420 88.365 23.435 ;
        RECT 88.810 23.420 89.170 23.440 ;
        RECT 84.440 23.190 89.440 23.420 ;
        RECT 87.150 23.175 87.510 23.190 ;
        RECT 88.005 23.175 88.365 23.190 ;
        RECT 88.810 23.180 89.170 23.190 ;
        RECT 84.660 22.630 85.020 22.645 ;
        RECT 85.430 22.630 85.790 22.645 ;
        RECT 86.210 22.630 86.570 22.645 ;
        RECT 84.440 22.400 89.440 22.630 ;
        RECT 84.660 22.385 85.020 22.400 ;
        RECT 85.430 22.385 85.790 22.400 ;
        RECT 86.210 22.385 86.570 22.400 ;
        RECT 87.150 21.840 87.510 21.855 ;
        RECT 88.005 21.840 88.365 21.855 ;
        RECT 88.810 21.840 89.170 21.855 ;
        RECT 84.440 21.610 89.440 21.840 ;
        RECT 87.150 21.595 87.510 21.610 ;
        RECT 88.005 21.595 88.365 21.610 ;
        RECT 88.810 21.595 89.170 21.610 ;
        RECT 84.660 21.050 85.020 21.065 ;
        RECT 85.430 21.050 85.790 21.065 ;
        RECT 86.210 21.050 86.570 21.065 ;
        RECT 84.440 20.820 89.440 21.050 ;
        RECT 84.660 20.805 85.020 20.820 ;
        RECT 85.430 20.805 85.790 20.820 ;
        RECT 86.210 20.805 86.570 20.820 ;
        RECT 87.150 20.260 87.510 20.270 ;
        RECT 88.010 20.260 88.370 20.270 ;
        RECT 88.810 20.260 89.170 20.270 ;
        RECT 84.440 20.030 89.440 20.260 ;
        RECT 87.150 20.010 87.510 20.030 ;
        RECT 88.010 20.010 88.370 20.030 ;
        RECT 88.810 20.010 89.170 20.030 ;
        RECT 89.580 19.510 89.880 25.690 ;
        RECT 92.000 19.510 92.300 25.700 ;
        RECT 92.440 25.560 97.440 25.790 ;
        RECT 92.660 25.550 93.020 25.560 ;
        RECT 93.430 25.550 93.790 25.560 ;
        RECT 94.210 25.550 94.570 25.560 ;
        RECT 95.150 25.000 95.510 25.015 ;
        RECT 96.005 25.000 96.365 25.015 ;
        RECT 96.810 25.000 97.170 25.010 ;
        RECT 92.440 24.770 97.440 25.000 ;
        RECT 95.150 24.755 95.510 24.770 ;
        RECT 96.005 24.755 96.365 24.770 ;
        RECT 96.810 24.750 97.170 24.770 ;
        RECT 92.660 24.210 93.020 24.225 ;
        RECT 93.430 24.210 93.790 24.225 ;
        RECT 94.210 24.210 94.570 24.225 ;
        RECT 92.440 23.980 97.440 24.210 ;
        RECT 92.660 23.965 93.020 23.980 ;
        RECT 93.430 23.965 93.790 23.980 ;
        RECT 94.210 23.965 94.570 23.980 ;
        RECT 95.150 23.420 95.510 23.435 ;
        RECT 96.005 23.420 96.365 23.435 ;
        RECT 96.810 23.420 97.170 23.440 ;
        RECT 92.440 23.190 97.440 23.420 ;
        RECT 95.150 23.175 95.510 23.190 ;
        RECT 96.005 23.175 96.365 23.190 ;
        RECT 96.810 23.180 97.170 23.190 ;
        RECT 92.660 22.630 93.020 22.645 ;
        RECT 93.430 22.630 93.790 22.645 ;
        RECT 94.210 22.630 94.570 22.645 ;
        RECT 92.440 22.400 97.440 22.630 ;
        RECT 92.660 22.385 93.020 22.400 ;
        RECT 93.430 22.385 93.790 22.400 ;
        RECT 94.210 22.385 94.570 22.400 ;
        RECT 95.150 21.840 95.510 21.855 ;
        RECT 96.005 21.840 96.365 21.855 ;
        RECT 96.810 21.840 97.170 21.855 ;
        RECT 92.440 21.610 97.440 21.840 ;
        RECT 95.150 21.595 95.510 21.610 ;
        RECT 96.005 21.595 96.365 21.610 ;
        RECT 96.810 21.595 97.170 21.610 ;
        RECT 92.660 21.050 93.020 21.065 ;
        RECT 93.430 21.050 93.790 21.065 ;
        RECT 94.210 21.050 94.570 21.065 ;
        RECT 92.440 20.820 97.440 21.050 ;
        RECT 92.660 20.805 93.020 20.820 ;
        RECT 93.430 20.805 93.790 20.820 ;
        RECT 94.210 20.805 94.570 20.820 ;
        RECT 95.150 20.260 95.510 20.270 ;
        RECT 96.010 20.260 96.370 20.270 ;
        RECT 96.810 20.260 97.170 20.270 ;
        RECT 92.440 20.030 97.440 20.260 ;
        RECT 95.150 20.010 95.510 20.030 ;
        RECT 96.010 20.010 96.370 20.030 ;
        RECT 96.810 20.010 97.170 20.030 ;
        RECT 97.580 19.510 97.880 25.710 ;
        RECT 100.000 19.510 100.300 25.720 ;
        RECT 100.440 25.560 105.440 25.790 ;
        RECT 100.660 25.550 101.020 25.560 ;
        RECT 101.430 25.550 101.790 25.560 ;
        RECT 102.210 25.550 102.570 25.560 ;
        RECT 103.150 25.000 103.510 25.015 ;
        RECT 104.005 25.000 104.365 25.015 ;
        RECT 104.810 25.000 105.170 25.010 ;
        RECT 100.440 24.770 105.440 25.000 ;
        RECT 103.150 24.755 103.510 24.770 ;
        RECT 104.005 24.755 104.365 24.770 ;
        RECT 104.810 24.750 105.170 24.770 ;
        RECT 100.660 24.210 101.020 24.225 ;
        RECT 101.430 24.210 101.790 24.225 ;
        RECT 102.210 24.210 102.570 24.225 ;
        RECT 100.440 23.980 105.440 24.210 ;
        RECT 100.660 23.965 101.020 23.980 ;
        RECT 101.430 23.965 101.790 23.980 ;
        RECT 102.210 23.965 102.570 23.980 ;
        RECT 103.150 23.420 103.510 23.435 ;
        RECT 104.005 23.420 104.365 23.435 ;
        RECT 104.810 23.420 105.170 23.440 ;
        RECT 100.440 23.190 105.440 23.420 ;
        RECT 103.150 23.175 103.510 23.190 ;
        RECT 104.005 23.175 104.365 23.190 ;
        RECT 104.810 23.180 105.170 23.190 ;
        RECT 100.660 22.630 101.020 22.645 ;
        RECT 101.430 22.630 101.790 22.645 ;
        RECT 102.210 22.630 102.570 22.645 ;
        RECT 100.440 22.400 105.440 22.630 ;
        RECT 100.660 22.385 101.020 22.400 ;
        RECT 101.430 22.385 101.790 22.400 ;
        RECT 102.210 22.385 102.570 22.400 ;
        RECT 103.150 21.840 103.510 21.855 ;
        RECT 104.005 21.840 104.365 21.855 ;
        RECT 104.810 21.840 105.170 21.855 ;
        RECT 100.440 21.610 105.440 21.840 ;
        RECT 103.150 21.595 103.510 21.610 ;
        RECT 104.005 21.595 104.365 21.610 ;
        RECT 104.810 21.595 105.170 21.610 ;
        RECT 100.660 21.050 101.020 21.065 ;
        RECT 101.430 21.050 101.790 21.065 ;
        RECT 102.210 21.050 102.570 21.065 ;
        RECT 100.440 20.820 105.440 21.050 ;
        RECT 100.660 20.805 101.020 20.820 ;
        RECT 101.430 20.805 101.790 20.820 ;
        RECT 102.210 20.805 102.570 20.820 ;
        RECT 103.150 20.260 103.510 20.270 ;
        RECT 104.010 20.260 104.370 20.270 ;
        RECT 104.810 20.260 105.170 20.270 ;
        RECT 100.440 20.030 105.440 20.260 ;
        RECT 103.150 20.010 103.510 20.030 ;
        RECT 104.010 20.010 104.370 20.030 ;
        RECT 104.810 20.010 105.170 20.030 ;
        RECT 105.580 19.510 105.880 25.710 ;
        RECT 108.000 19.510 108.300 25.710 ;
        RECT 108.440 25.560 113.440 25.790 ;
        RECT 108.660 25.550 109.020 25.560 ;
        RECT 109.430 25.550 109.790 25.560 ;
        RECT 110.210 25.550 110.570 25.560 ;
        RECT 111.150 25.000 111.510 25.015 ;
        RECT 112.005 25.000 112.365 25.015 ;
        RECT 112.810 25.000 113.170 25.010 ;
        RECT 108.440 24.770 113.440 25.000 ;
        RECT 111.150 24.755 111.510 24.770 ;
        RECT 112.005 24.755 112.365 24.770 ;
        RECT 112.810 24.750 113.170 24.770 ;
        RECT 108.660 24.210 109.020 24.225 ;
        RECT 109.430 24.210 109.790 24.225 ;
        RECT 110.210 24.210 110.570 24.225 ;
        RECT 108.440 23.980 113.440 24.210 ;
        RECT 108.660 23.965 109.020 23.980 ;
        RECT 109.430 23.965 109.790 23.980 ;
        RECT 110.210 23.965 110.570 23.980 ;
        RECT 111.150 23.420 111.510 23.435 ;
        RECT 112.005 23.420 112.365 23.435 ;
        RECT 112.810 23.420 113.170 23.440 ;
        RECT 108.440 23.190 113.440 23.420 ;
        RECT 111.150 23.175 111.510 23.190 ;
        RECT 112.005 23.175 112.365 23.190 ;
        RECT 112.810 23.180 113.170 23.190 ;
        RECT 108.660 22.630 109.020 22.645 ;
        RECT 109.430 22.630 109.790 22.645 ;
        RECT 110.210 22.630 110.570 22.645 ;
        RECT 108.440 22.400 113.440 22.630 ;
        RECT 108.660 22.385 109.020 22.400 ;
        RECT 109.430 22.385 109.790 22.400 ;
        RECT 110.210 22.385 110.570 22.400 ;
        RECT 111.150 21.840 111.510 21.855 ;
        RECT 112.005 21.840 112.365 21.855 ;
        RECT 112.810 21.840 113.170 21.855 ;
        RECT 108.440 21.610 113.440 21.840 ;
        RECT 111.150 21.595 111.510 21.610 ;
        RECT 112.005 21.595 112.365 21.610 ;
        RECT 112.810 21.595 113.170 21.610 ;
        RECT 108.660 21.050 109.020 21.065 ;
        RECT 109.430 21.050 109.790 21.065 ;
        RECT 110.210 21.050 110.570 21.065 ;
        RECT 108.440 20.820 113.440 21.050 ;
        RECT 108.660 20.805 109.020 20.820 ;
        RECT 109.430 20.805 109.790 20.820 ;
        RECT 110.210 20.805 110.570 20.820 ;
        RECT 111.150 20.260 111.510 20.270 ;
        RECT 112.010 20.260 112.370 20.270 ;
        RECT 112.810 20.260 113.170 20.270 ;
        RECT 108.440 20.030 113.440 20.260 ;
        RECT 111.150 20.010 111.510 20.030 ;
        RECT 112.010 20.010 112.370 20.030 ;
        RECT 112.810 20.010 113.170 20.030 ;
        RECT 113.580 19.510 113.880 25.700 ;
        RECT 114.130 25.520 115.250 27.040 ;
        RECT 52.000 19.210 113.880 19.510 ;
        RECT 52.465 18.470 54.705 19.210 ;
        RECT 51.390 16.200 52.730 17.510 ;
        RECT 63.550 16.180 64.800 17.510 ;
        RECT 78.870 16.220 80.100 17.510 ;
        RECT 97.130 16.290 98.460 17.500 ;
        RECT 113.010 16.380 114.340 17.520 ;
      LAYER met2 ;
        RECT 75.850 88.150 86.950 93.900 ;
        RECT 87.240 90.560 88.620 92.420 ;
        RECT 77.820 82.090 78.990 83.250 ;
        RECT 79.835 81.750 85.995 84.930 ;
        RECT 86.790 82.040 88.010 83.280 ;
        RECT 70.860 79.860 85.995 81.750 ;
        RECT 69.020 77.520 70.100 78.490 ;
        RECT 70.865 75.580 95.275 79.860 ;
        RECT 96.150 77.610 97.190 78.690 ;
        RECT 81.190 71.220 82.190 72.400 ;
        RECT 84.020 71.150 85.040 72.430 ;
        RECT 69.070 67.160 70.110 68.240 ;
        RECT 70.840 66.970 81.190 69.990 ;
        RECT 84.860 68.110 102.030 69.980 ;
        RECT 84.860 66.980 95.210 68.110 ;
        RECT 70.840 66.560 82.810 66.970 ;
        RECT 55.680 63.710 56.720 64.790 ;
        RECT 70.240 63.810 71.280 64.890 ;
        RECT 74.820 61.570 82.810 66.560 ;
        RECT 83.260 66.550 95.210 66.980 ;
        RECT 96.260 66.730 97.300 67.810 ;
        RECT 83.260 61.580 91.230 66.550 ;
        RECT 94.060 63.740 95.100 64.820 ;
        RECT 74.820 61.560 81.190 61.570 ;
        RECT 84.860 61.560 91.230 61.580 ;
        RECT 108.350 61.560 109.390 62.640 ;
        RECT 55.700 52.470 56.740 53.550 ;
        RECT 60.840 50.160 62.980 58.980 ;
        RECT 58.760 49.860 62.980 50.160 ;
        RECT 42.610 34.550 43.650 35.630 ;
        RECT 55.240 33.800 56.280 34.880 ;
        RECT 38.560 27.850 45.480 33.620 ;
        RECT 51.985 33.590 52.495 33.600 ;
        RECT 51.985 27.870 54.695 33.590 ;
        RECT 57.080 30.200 58.120 31.280 ;
        RECT 42.620 25.940 43.660 27.020 ;
        RECT 52.465 18.470 54.695 27.870 ;
        RECT 56.290 26.440 57.330 27.520 ;
        RECT 54.920 17.880 57.340 25.850 ;
        RECT 51.500 16.190 52.540 17.270 ;
        RECT 58.760 10.460 59.060 49.860 ;
        RECT 60.840 40.840 62.980 49.860 ;
        RECT 70.650 58.610 81.130 60.630 ;
        RECT 70.650 52.600 74.510 58.610 ;
        RECT 84.840 58.520 94.500 60.790 ;
        RECT 91.390 55.500 94.500 58.520 ;
        RECT 74.820 53.320 84.450 55.320 ;
        RECT 84.790 53.230 94.500 55.500 ;
        RECT 70.650 50.580 81.170 52.600 ;
        RECT 70.650 44.490 74.510 50.580 ;
        RECT 81.570 50.570 91.100 52.900 ;
        RECT 87.460 48.400 89.600 49.510 ;
        RECT 74.840 45.170 82.770 47.370 ;
        RECT 83.280 45.230 91.100 47.380 ;
        RECT 91.390 44.760 94.500 53.230 ;
        RECT 102.030 49.720 104.130 58.900 ;
        RECT 102.030 49.420 115.750 49.720 ;
        RECT 70.650 42.470 81.150 44.490 ;
        RECT 84.860 42.490 94.520 44.760 ;
        RECT 70.650 36.610 74.510 42.470 ;
        RECT 76.450 40.340 78.590 41.450 ;
        RECT 91.390 39.470 94.500 42.490 ;
        RECT 102.030 40.880 104.130 49.420 ;
        RECT 108.340 46.180 109.380 47.260 ;
        RECT 74.820 37.430 84.440 39.320 ;
        RECT 84.790 37.200 94.500 39.470 ;
        RECT 70.650 34.590 81.190 36.610 ;
        RECT 70.650 31.860 74.510 34.590 ;
        RECT 81.540 34.510 91.100 36.920 ;
        RECT 91.390 31.860 94.500 37.200 ;
        RECT 108.310 32.370 109.350 33.450 ;
        RECT 60.520 26.500 110.770 31.860 ;
        RECT 60.530 19.870 62.730 26.500 ;
        RECT 63.030 17.910 65.450 25.880 ;
        RECT 68.540 19.840 70.740 26.500 ;
        RECT 71.010 17.900 73.430 25.870 ;
        RECT 76.500 19.850 78.700 26.500 ;
        RECT 79.020 17.910 81.440 25.880 ;
        RECT 82.380 25.120 83.420 26.200 ;
        RECT 84.520 19.880 86.720 26.500 ;
        RECT 87.040 17.910 89.460 25.880 ;
        RECT 92.490 19.840 94.690 26.500 ;
        RECT 95.000 17.900 97.420 25.870 ;
        RECT 100.550 19.840 102.750 26.500 ;
        RECT 103.030 17.920 105.450 25.890 ;
        RECT 108.570 19.860 110.770 26.500 ;
        RECT 114.190 26.190 115.230 27.270 ;
        RECT 111.020 17.870 113.440 25.840 ;
        RECT 63.660 16.280 64.700 17.360 ;
        RECT 78.990 16.260 80.030 17.340 ;
        RECT 97.290 16.310 98.330 17.390 ;
        RECT 113.110 16.400 114.150 17.480 ;
        RECT 115.445 10.580 115.750 49.420 ;
        RECT 58.760 10.160 94.410 10.460 ;
        RECT 94.110 9.220 94.410 10.160 ;
        RECT 113.310 10.280 115.750 10.580 ;
        RECT 93.930 8.310 94.640 9.220 ;
        RECT 113.310 8.850 113.610 10.280 ;
        RECT 113.130 7.930 113.720 8.850 ;
      LAYER met3 ;
        RECT 71.600 87.150 78.280 94.750 ;
        RECT 87.230 90.580 88.610 92.450 ;
        RECT 37.380 79.090 73.400 82.810 ;
        RECT 77.790 82.010 78.970 83.270 ;
        RECT 86.810 81.970 88.090 83.350 ;
        RECT 37.380 78.900 68.530 79.090 ;
        RECT 70.420 78.900 73.400 79.090 ;
        RECT 37.380 27.630 41.580 78.900 ;
        RECT 68.990 77.470 70.100 78.550 ;
        RECT 96.140 77.600 97.190 78.690 ;
        RECT 81.190 71.220 82.260 72.440 ;
        RECT 83.990 71.120 85.050 72.470 ;
        RECT 82.010 68.580 98.860 69.250 ;
        RECT 69.060 67.150 70.110 68.240 ;
        RECT 82.010 66.990 82.560 68.580 ;
        RECT 55.670 63.700 56.720 64.790 ;
        RECT 70.230 63.800 71.280 64.890 ;
        RECT 55.690 52.460 56.740 53.550 ;
        RECT 76.460 40.340 78.590 41.450 ;
        RECT 42.600 34.540 43.650 35.630 ;
        RECT 55.230 33.790 56.280 34.880 ;
        RECT 79.610 33.990 82.810 66.990 ;
        RECT 83.260 33.990 86.460 66.990 ;
        RECT 96.250 66.720 97.300 67.810 ;
        RECT 94.050 63.730 95.100 64.820 ;
        RECT 98.340 63.750 98.860 68.580 ;
        RECT 100.120 67.640 102.100 69.980 ;
        RECT 101.340 66.990 102.100 67.640 ;
        RECT 101.340 66.020 145.560 66.990 ;
        RECT 98.340 62.950 133.400 63.750 ;
        RECT 108.340 61.550 109.390 62.640 ;
        RECT 87.460 48.400 89.590 49.510 ;
        RECT 108.330 46.170 109.380 47.260 ;
        RECT 108.300 32.360 109.350 33.450 ;
        RECT 57.070 30.190 58.120 31.280 ;
        RECT 42.610 25.930 43.660 27.020 ;
        RECT 56.280 26.430 57.330 27.520 ;
        RECT 82.370 25.110 83.420 26.200 ;
        RECT 114.180 26.180 115.230 27.270 ;
        RECT 54.920 17.870 57.330 19.170 ;
        RECT 63.030 17.910 65.440 19.180 ;
        RECT 71.020 17.940 73.410 19.200 ;
        RECT 79.030 17.920 81.420 19.180 ;
        RECT 87.050 17.940 89.440 19.200 ;
        RECT 95.010 17.900 97.400 19.160 ;
        RECT 103.040 17.960 105.430 19.220 ;
        RECT 111.030 17.900 113.420 19.160 ;
        RECT 51.490 16.180 52.540 17.270 ;
        RECT 63.650 16.270 64.700 17.360 ;
        RECT 78.980 16.250 80.030 17.340 ;
        RECT 97.280 16.300 98.330 17.390 ;
        RECT 113.100 16.390 114.150 17.480 ;
        RECT 93.960 2.000 94.640 9.220 ;
        RECT 113.260 8.345 113.990 8.810 ;
        RECT 113.255 8.015 113.990 8.345 ;
        RECT 113.260 2.590 113.990 8.015 ;
        RECT 132.480 7.700 133.400 62.950 ;
        RECT 132.660 3.990 133.400 7.700 ;
        RECT 131.610 2.450 133.520 3.990 ;
        RECT 144.400 2.000 145.560 66.020 ;
        RECT 151.590 2.000 152.970 2.890 ;
        RECT 144.400 1.320 152.970 2.000 ;
        RECT 151.590 1.310 152.970 1.320 ;
      LAYER met4 ;
        RECT 30.670 220.740 30.970 224.760 ;
        RECT 33.430 220.740 33.730 224.760 ;
        RECT 36.190 220.740 36.490 224.760 ;
        RECT 38.950 220.740 39.250 224.760 ;
        RECT 41.710 220.740 42.010 224.760 ;
        RECT 44.470 220.740 44.770 224.760 ;
        RECT 47.230 220.740 47.530 224.760 ;
        RECT 49.990 220.740 50.290 224.760 ;
        RECT 52.750 220.740 53.050 224.760 ;
        RECT 55.510 220.740 55.810 224.760 ;
        RECT 58.270 220.740 58.570 224.760 ;
        RECT 61.030 220.740 61.330 224.760 ;
        RECT 63.790 220.740 64.090 224.760 ;
        RECT 66.550 220.740 66.850 224.760 ;
        RECT 69.310 220.740 69.610 224.760 ;
        RECT 72.070 220.740 72.370 224.760 ;
        RECT 74.830 220.740 75.130 224.760 ;
        RECT 77.590 220.740 77.890 224.760 ;
        RECT 80.350 220.740 80.650 224.760 ;
        RECT 83.110 220.740 83.410 224.760 ;
        RECT 85.870 220.740 86.170 224.760 ;
        RECT 88.630 220.740 88.930 224.760 ;
        RECT 91.390 220.740 91.690 224.760 ;
        RECT 94.150 220.740 94.450 224.760 ;
        RECT 96.910 220.740 97.210 220.750 ;
        RECT 99.670 220.740 99.970 220.750 ;
        RECT 102.430 220.740 102.730 220.750 ;
        RECT 105.190 220.740 105.490 220.750 ;
        RECT 107.950 220.740 108.250 220.750 ;
        RECT 110.710 220.740 111.010 220.750 ;
        RECT 113.470 220.740 113.770 220.750 ;
        RECT 116.230 220.740 116.530 220.750 ;
        RECT 118.990 220.740 119.290 220.750 ;
        RECT 121.750 220.740 122.050 220.750 ;
        RECT 124.510 220.740 124.810 220.750 ;
        RECT 30.670 219.560 152.250 220.740 ;
        RECT 8.100 86.360 74.080 95.440 ;
        RECT 86.240 83.270 89.390 93.470 ;
        RECT 54.020 74.040 152.250 83.270 ;
        RECT 54.020 73.950 72.320 74.040 ;
        RECT 54.030 51.180 59.100 73.950 ;
        RECT 67.240 62.920 72.320 73.950 ;
        RECT 81.190 72.200 82.380 74.040 ;
        RECT 81.190 71.200 82.300 72.200 ;
        RECT 83.940 71.070 85.040 74.040 ;
        RECT 93.240 63.010 97.830 74.040 ;
        RECT 107.150 60.700 110.690 74.040 ;
        RECT 42.180 33.530 59.110 36.300 ;
        RECT 75.080 33.530 79.310 41.780 ;
        RECT 86.280 33.530 90.960 49.800 ;
        RECT 107.150 33.530 110.780 47.810 ;
        RECT 42.180 27.040 152.250 33.530 ;
        RECT 42.180 24.960 115.440 27.040 ;
        RECT 51.090 15.710 115.440 24.960 ;
        RECT 93.960 1.000 94.640 2.990 ;
        RECT 113.270 1.000 113.940 3.740 ;
        RECT 131.610 2.450 133.520 3.990 ;
        RECT 132.670 1.000 133.340 2.450 ;
        RECT 151.590 1.310 152.970 2.890 ;
        RECT 151.700 1.000 152.750 1.310 ;
        RECT 151.700 0.960 151.810 1.000 ;
        RECT 152.710 0.960 152.750 1.000 ;
  END
END tt_um_mbotros_diff_amp_lvt
END LIBRARY

